VERSION 5.7 ;
BUSBITCHARS "[]" ;
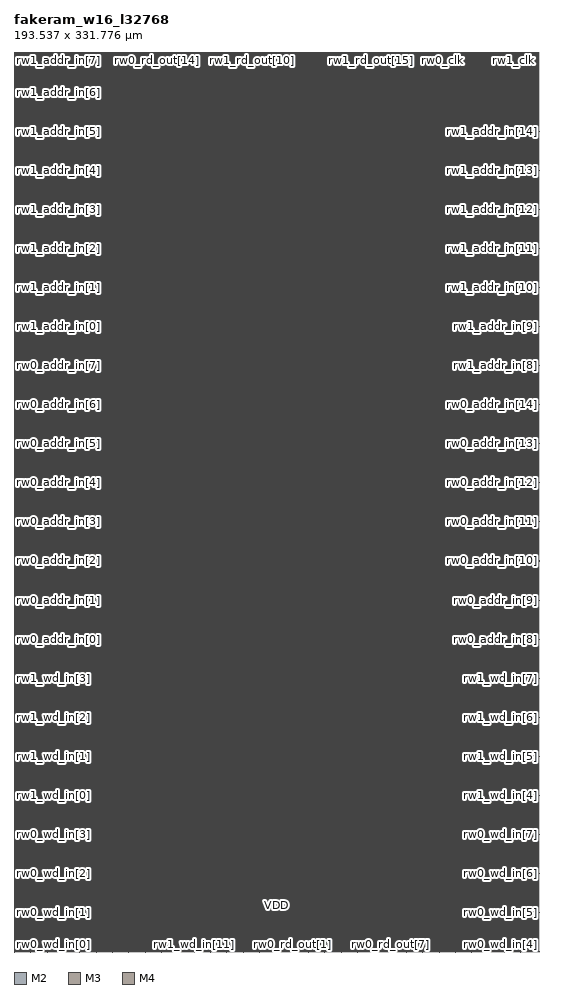
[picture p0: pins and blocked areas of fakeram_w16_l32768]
MACRO fakeram_w16_l32768
  FOREIGN fakeram_w16_l32768 0 0 ;
  SYMMETRY X Y R90 ;
  SIZE 193.537 BY 331.776 ;
  CLASS BLOCK ;
  PIN rw0_wd_in[0]
    DIRECTION INPUT ;
    USE SIGNAL ;
    SHAPE ABUTMENT ;
    PORT
      LAYER M2 ;
      RECT 0.000 0.138 0.036 0.150 ;
    END
  END rw0_wd_in[0]
  PIN rw0_wd_in[1]
    DIRECTION INPUT ;
    USE SIGNAL ;
    SHAPE ABUTMENT ;
    PORT
      LAYER M2 ;
      RECT 0.000 14.538 0.036 14.550 ;
    END
  END rw0_wd_in[1]
  PIN rw0_wd_in[2]
    DIRECTION INPUT ;
    USE SIGNAL ;
    SHAPE ABUTMENT ;
    PORT
      LAYER M2 ;
      RECT 0.000 28.938 0.036 28.950 ;
    END
  END rw0_wd_in[2]
  PIN rw0_wd_in[3]
    DIRECTION INPUT ;
    USE SIGNAL ;
    SHAPE ABUTMENT ;
    PORT
      LAYER M2 ;
      RECT 0.000 43.338 0.036 43.350 ;
    END
  END rw0_wd_in[3]
  PIN rw0_wd_in[4]
    DIRECTION INPUT ;
    USE SIGNAL ;
    SHAPE ABUTMENT ;
    PORT
      LAYER M2 ;
      RECT 193.501 0.138 193.537 0.150 ;
    END
  END rw0_wd_in[4]
  PIN rw0_wd_in[5]
    DIRECTION INPUT ;
    USE SIGNAL ;
    SHAPE ABUTMENT ;
    PORT
      LAYER M2 ;
      RECT 193.501 14.538 193.537 14.550 ;
    END
  END rw0_wd_in[5]
  PIN rw0_wd_in[6]
    DIRECTION INPUT ;
    USE SIGNAL ;
    SHAPE ABUTMENT ;
    PORT
      LAYER M2 ;
      RECT 193.501 28.938 193.537 28.950 ;
    END
  END rw0_wd_in[6]
  PIN rw0_wd_in[7]
    DIRECTION INPUT ;
    USE SIGNAL ;
    SHAPE ABUTMENT ;
    PORT
      LAYER M2 ;
      RECT 193.501 43.338 193.537 43.350 ;
    END
  END rw0_wd_in[7]
  PIN rw0_wd_in[8]
    DIRECTION INPUT ;
    USE SIGNAL ;
    SHAPE ABUTMENT ;
    PORT
      LAYER M3 ;
      RECT 0.161 0.000 0.175 0.042 ;
    END
  END rw0_wd_in[8]
  PIN rw0_wd_in[9]
    DIRECTION INPUT ;
    USE SIGNAL ;
    SHAPE ABUTMENT ;
    PORT
      LAYER M3 ;
      RECT 6.181 0.000 6.195 0.042 ;
    END
  END rw0_wd_in[9]
  PIN rw0_wd_in[10]
    DIRECTION INPUT ;
    USE SIGNAL ;
    SHAPE ABUTMENT ;
    PORT
      LAYER M3 ;
      RECT 12.201 0.000 12.215 0.042 ;
    END
  END rw0_wd_in[10]
  PIN rw0_wd_in[11]
    DIRECTION INPUT ;
    USE SIGNAL ;
    SHAPE ABUTMENT ;
    PORT
      LAYER M3 ;
      RECT 18.221 0.000 18.235 0.042 ;
    END
  END rw0_wd_in[11]
  PIN rw0_wd_in[12]
    DIRECTION INPUT ;
    USE SIGNAL ;
    SHAPE ABUTMENT ;
    PORT
      LAYER M3 ;
      RECT 24.241 0.000 24.255 0.042 ;
    END
  END rw0_wd_in[12]
  PIN rw0_wd_in[13]
    DIRECTION INPUT ;
    USE SIGNAL ;
    SHAPE ABUTMENT ;
    PORT
      LAYER M3 ;
      RECT 30.261 0.000 30.275 0.042 ;
    END
  END rw0_wd_in[13]
  PIN rw0_wd_in[14]
    DIRECTION INPUT ;
    USE SIGNAL ;
    SHAPE ABUTMENT ;
    PORT
      LAYER M3 ;
      RECT 36.281 0.000 36.295 0.042 ;
    END
  END rw0_wd_in[14]
  PIN rw0_wd_in[15]
    DIRECTION INPUT ;
    USE SIGNAL ;
    SHAPE ABUTMENT ;
    PORT
      LAYER M3 ;
      RECT 42.301 0.000 42.315 0.042 ;
    END
  END rw0_wd_in[15]
  PIN rw1_wd_in[0]
    DIRECTION INPUT ;
    USE SIGNAL ;
    SHAPE ABUTMENT ;
    PORT
      LAYER M2 ;
      RECT 0.000 57.738 0.036 57.750 ;
    END
  END rw1_wd_in[0]
  PIN rw1_wd_in[1]
    DIRECTION INPUT ;
    USE SIGNAL ;
    SHAPE ABUTMENT ;
    PORT
      LAYER M2 ;
      RECT 0.000 72.138 0.036 72.150 ;
    END
  END rw1_wd_in[1]
  PIN rw1_wd_in[2]
    DIRECTION INPUT ;
    USE SIGNAL ;
    SHAPE ABUTMENT ;
    PORT
      LAYER M2 ;
      RECT 0.000 86.538 0.036 86.550 ;
    END
  END rw1_wd_in[2]
  PIN rw1_wd_in[3]
    DIRECTION INPUT ;
    USE SIGNAL ;
    SHAPE ABUTMENT ;
    PORT
      LAYER M2 ;
      RECT 0.000 100.938 0.036 100.950 ;
    END
  END rw1_wd_in[3]
  PIN rw1_wd_in[4]
    DIRECTION INPUT ;
    USE SIGNAL ;
    SHAPE ABUTMENT ;
    PORT
      LAYER M2 ;
      RECT 193.501 57.738 193.537 57.750 ;
    END
  END rw1_wd_in[4]
  PIN rw1_wd_in[5]
    DIRECTION INPUT ;
    USE SIGNAL ;
    SHAPE ABUTMENT ;
    PORT
      LAYER M2 ;
      RECT 193.501 72.138 193.537 72.150 ;
    END
  END rw1_wd_in[5]
  PIN rw1_wd_in[6]
    DIRECTION INPUT ;
    USE SIGNAL ;
    SHAPE ABUTMENT ;
    PORT
      LAYER M2 ;
      RECT 193.501 86.538 193.537 86.550 ;
    END
  END rw1_wd_in[6]
  PIN rw1_wd_in[7]
    DIRECTION INPUT ;
    USE SIGNAL ;
    SHAPE ABUTMENT ;
    PORT
      LAYER M2 ;
      RECT 193.501 100.938 193.537 100.950 ;
    END
  END rw1_wd_in[7]
  PIN rw1_wd_in[8]
    DIRECTION INPUT ;
    USE SIGNAL ;
    SHAPE ABUTMENT ;
    PORT
      LAYER M3 ;
      RECT 48.321 0.000 48.335 0.042 ;
    END
  END rw1_wd_in[8]
  PIN rw1_wd_in[9]
    DIRECTION INPUT ;
    USE SIGNAL ;
    SHAPE ABUTMENT ;
    PORT
      LAYER M3 ;
      RECT 54.341 0.000 54.355 0.042 ;
    END
  END rw1_wd_in[9]
  PIN rw1_wd_in[10]
    DIRECTION INPUT ;
    USE SIGNAL ;
    SHAPE ABUTMENT ;
    PORT
      LAYER M3 ;
      RECT 60.361 0.000 60.375 0.042 ;
    END
  END rw1_wd_in[10]
  PIN rw1_wd_in[11]
    DIRECTION INPUT ;
    USE SIGNAL ;
    SHAPE ABUTMENT ;
    PORT
      LAYER M3 ;
      RECT 66.381 0.000 66.395 0.042 ;
    END
  END rw1_wd_in[11]
  PIN rw1_wd_in[12]
    DIRECTION INPUT ;
    USE SIGNAL ;
    SHAPE ABUTMENT ;
    PORT
      LAYER M3 ;
      RECT 72.401 0.000 72.415 0.042 ;
    END
  END rw1_wd_in[12]
  PIN rw1_wd_in[13]
    DIRECTION INPUT ;
    USE SIGNAL ;
    SHAPE ABUTMENT ;
    PORT
      LAYER M3 ;
      RECT 78.421 0.000 78.435 0.042 ;
    END
  END rw1_wd_in[13]
  PIN rw1_wd_in[14]
    DIRECTION INPUT ;
    USE SIGNAL ;
    SHAPE ABUTMENT ;
    PORT
      LAYER M3 ;
      RECT 84.441 0.000 84.455 0.042 ;
    END
  END rw1_wd_in[14]
  PIN rw1_wd_in[15]
    DIRECTION INPUT ;
    USE SIGNAL ;
    SHAPE ABUTMENT ;
    PORT
      LAYER M3 ;
      RECT 90.461 0.000 90.475 0.042 ;
    END
  END rw1_wd_in[15]
  PIN rw0_rd_out[0]
    DIRECTION OUTPUT ;
    USE SIGNAL ;
    SHAPE ABUTMENT ;
    PORT
      LAYER M3 ;
      RECT 96.481 0.000 96.495 0.042 ;
    END
  END rw0_rd_out[0]
  PIN rw0_rd_out[1]
    DIRECTION OUTPUT ;
    USE SIGNAL ;
    SHAPE ABUTMENT ;
    PORT
      LAYER M3 ;
      RECT 102.501 0.000 102.515 0.042 ;
    END
  END rw0_rd_out[1]
  PIN rw0_rd_out[2]
    DIRECTION OUTPUT ;
    USE SIGNAL ;
    SHAPE ABUTMENT ;
    PORT
      LAYER M3 ;
      RECT 108.521 0.000 108.535 0.042 ;
    END
  END rw0_rd_out[2]
  PIN rw0_rd_out[3]
    DIRECTION OUTPUT ;
    USE SIGNAL ;
    SHAPE ABUTMENT ;
    PORT
      LAYER M3 ;
      RECT 114.541 0.000 114.555 0.042 ;
    END
  END rw0_rd_out[3]
  PIN rw0_rd_out[4]
    DIRECTION OUTPUT ;
    USE SIGNAL ;
    SHAPE ABUTMENT ;
    PORT
      LAYER M3 ;
      RECT 120.561 0.000 120.575 0.042 ;
    END
  END rw0_rd_out[4]
  PIN rw0_rd_out[5]
    DIRECTION OUTPUT ;
    USE SIGNAL ;
    SHAPE ABUTMENT ;
    PORT
      LAYER M3 ;
      RECT 126.581 0.000 126.595 0.042 ;
    END
  END rw0_rd_out[5]
  PIN rw0_rd_out[6]
    DIRECTION OUTPUT ;
    USE SIGNAL ;
    SHAPE ABUTMENT ;
    PORT
      LAYER M3 ;
      RECT 132.601 0.000 132.615 0.042 ;
    END
  END rw0_rd_out[6]
  PIN rw0_rd_out[7]
    DIRECTION OUTPUT ;
    USE SIGNAL ;
    SHAPE ABUTMENT ;
    PORT
      LAYER M3 ;
      RECT 138.621 0.000 138.635 0.042 ;
    END
  END rw0_rd_out[7]
  PIN rw0_rd_out[8]
    DIRECTION OUTPUT ;
    USE SIGNAL ;
    SHAPE ABUTMENT ;
    PORT
      LAYER M3 ;
      RECT 0.161 331.734 0.175 331.776 ;
    END
  END rw0_rd_out[8]
  PIN rw0_rd_out[9]
    DIRECTION OUTPUT ;
    USE SIGNAL ;
    SHAPE ABUTMENT ;
    PORT
      LAYER M3 ;
      RECT 8.925 331.734 8.939 331.776 ;
    END
  END rw0_rd_out[9]
  PIN rw0_rd_out[10]
    DIRECTION OUTPUT ;
    USE SIGNAL ;
    SHAPE ABUTMENT ;
    PORT
      LAYER M3 ;
      RECT 17.689 331.734 17.703 331.776 ;
    END
  END rw0_rd_out[10]
  PIN rw0_rd_out[11]
    DIRECTION OUTPUT ;
    USE SIGNAL ;
    SHAPE ABUTMENT ;
    PORT
      LAYER M3 ;
      RECT 26.453 331.734 26.467 331.776 ;
    END
  END rw0_rd_out[11]
  PIN rw0_rd_out[12]
    DIRECTION OUTPUT ;
    USE SIGNAL ;
    SHAPE ABUTMENT ;
    PORT
      LAYER M3 ;
      RECT 35.217 331.734 35.231 331.776 ;
    END
  END rw0_rd_out[12]
  PIN rw0_rd_out[13]
    DIRECTION OUTPUT ;
    USE SIGNAL ;
    SHAPE ABUTMENT ;
    PORT
      LAYER M3 ;
      RECT 43.981 331.734 43.995 331.776 ;
    END
  END rw0_rd_out[13]
  PIN rw0_rd_out[14]
    DIRECTION OUTPUT ;
    USE SIGNAL ;
    SHAPE ABUTMENT ;
    PORT
      LAYER M3 ;
      RECT 52.745 331.734 52.759 331.776 ;
    END
  END rw0_rd_out[14]
  PIN rw0_rd_out[15]
    DIRECTION OUTPUT ;
    USE SIGNAL ;
    SHAPE ABUTMENT ;
    PORT
      LAYER M3 ;
      RECT 61.509 331.734 61.523 331.776 ;
    END
  END rw0_rd_out[15]
  PIN rw1_rd_out[0]
    DIRECTION OUTPUT ;
    USE SIGNAL ;
    SHAPE ABUTMENT ;
    PORT
      LAYER M3 ;
      RECT 144.641 0.000 144.655 0.042 ;
    END
  END rw1_rd_out[0]
  PIN rw1_rd_out[1]
    DIRECTION OUTPUT ;
    USE SIGNAL ;
    SHAPE ABUTMENT ;
    PORT
      LAYER M3 ;
      RECT 150.661 0.000 150.675 0.042 ;
    END
  END rw1_rd_out[1]
  PIN rw1_rd_out[2]
    DIRECTION OUTPUT ;
    USE SIGNAL ;
    SHAPE ABUTMENT ;
    PORT
      LAYER M3 ;
      RECT 156.681 0.000 156.695 0.042 ;
    END
  END rw1_rd_out[2]
  PIN rw1_rd_out[3]
    DIRECTION OUTPUT ;
    USE SIGNAL ;
    SHAPE ABUTMENT ;
    PORT
      LAYER M3 ;
      RECT 162.701 0.000 162.715 0.042 ;
    END
  END rw1_rd_out[3]
  PIN rw1_rd_out[4]
    DIRECTION OUTPUT ;
    USE SIGNAL ;
    SHAPE ABUTMENT ;
    PORT
      LAYER M3 ;
      RECT 168.721 0.000 168.735 0.042 ;
    END
  END rw1_rd_out[4]
  PIN rw1_rd_out[5]
    DIRECTION OUTPUT ;
    USE SIGNAL ;
    SHAPE ABUTMENT ;
    PORT
      LAYER M3 ;
      RECT 174.741 0.000 174.755 0.042 ;
    END
  END rw1_rd_out[5]
  PIN rw1_rd_out[6]
    DIRECTION OUTPUT ;
    USE SIGNAL ;
    SHAPE ABUTMENT ;
    PORT
      LAYER M3 ;
      RECT 180.761 0.000 180.775 0.042 ;
    END
  END rw1_rd_out[6]
  PIN rw1_rd_out[7]
    DIRECTION OUTPUT ;
    USE SIGNAL ;
    SHAPE ABUTMENT ;
    PORT
      LAYER M3 ;
      RECT 186.781 0.000 186.795 0.042 ;
    END
  END rw1_rd_out[7]
  PIN rw1_rd_out[8]
    DIRECTION OUTPUT ;
    USE SIGNAL ;
    SHAPE ABUTMENT ;
    PORT
      LAYER M3 ;
      RECT 70.273 331.734 70.287 331.776 ;
    END
  END rw1_rd_out[8]
  PIN rw1_rd_out[9]
    DIRECTION OUTPUT ;
    USE SIGNAL ;
    SHAPE ABUTMENT ;
    PORT
      LAYER M3 ;
      RECT 79.037 331.734 79.051 331.776 ;
    END
  END rw1_rd_out[9]
  PIN rw1_rd_out[10]
    DIRECTION OUTPUT ;
    USE SIGNAL ;
    SHAPE ABUTMENT ;
    PORT
      LAYER M3 ;
      RECT 87.801 331.734 87.815 331.776 ;
    END
  END rw1_rd_out[10]
  PIN rw1_rd_out[11]
    DIRECTION OUTPUT ;
    USE SIGNAL ;
    SHAPE ABUTMENT ;
    PORT
      LAYER M3 ;
      RECT 96.565 331.734 96.579 331.776 ;
    END
  END rw1_rd_out[11]
  PIN rw1_rd_out[12]
    DIRECTION OUTPUT ;
    USE SIGNAL ;
    SHAPE ABUTMENT ;
    PORT
      LAYER M3 ;
      RECT 105.329 331.734 105.343 331.776 ;
    END
  END rw1_rd_out[12]
  PIN rw1_rd_out[13]
    DIRECTION OUTPUT ;
    USE SIGNAL ;
    SHAPE ABUTMENT ;
    PORT
      LAYER M3 ;
      RECT 114.093 331.734 114.107 331.776 ;
    END
  END rw1_rd_out[13]
  PIN rw1_rd_out[14]
    DIRECTION OUTPUT ;
    USE SIGNAL ;
    SHAPE ABUTMENT ;
    PORT
      LAYER M3 ;
      RECT 122.857 331.734 122.871 331.776 ;
    END
  END rw1_rd_out[14]
  PIN rw1_rd_out[15]
    DIRECTION OUTPUT ;
    USE SIGNAL ;
    SHAPE ABUTMENT ;
    PORT
      LAYER M3 ;
      RECT 131.621 331.734 131.635 331.776 ;
    END
  END rw1_rd_out[15]
  PIN rw0_addr_in[0]
    DIRECTION INPUT ;
    USE SIGNAL ;
    SHAPE ABUTMENT ;
    PORT
      LAYER M2 ;
      RECT 0.000 115.338 0.036 115.350 ;
    END
  END rw0_addr_in[0]
  PIN rw0_addr_in[1]
    DIRECTION INPUT ;
    USE SIGNAL ;
    SHAPE ABUTMENT ;
    PORT
      LAYER M2 ;
      RECT 0.000 129.738 0.036 129.750 ;
    END
  END rw0_addr_in[1]
  PIN rw0_addr_in[2]
    DIRECTION INPUT ;
    USE SIGNAL ;
    SHAPE ABUTMENT ;
    PORT
      LAYER M2 ;
      RECT 0.000 144.138 0.036 144.150 ;
    END
  END rw0_addr_in[2]
  PIN rw0_addr_in[3]
    DIRECTION INPUT ;
    USE SIGNAL ;
    SHAPE ABUTMENT ;
    PORT
      LAYER M2 ;
      RECT 0.000 158.538 0.036 158.550 ;
    END
  END rw0_addr_in[3]
  PIN rw0_addr_in[4]
    DIRECTION INPUT ;
    USE SIGNAL ;
    SHAPE ABUTMENT ;
    PORT
      LAYER M2 ;
      RECT 0.000 172.938 0.036 172.950 ;
    END
  END rw0_addr_in[4]
  PIN rw0_addr_in[5]
    DIRECTION INPUT ;
    USE SIGNAL ;
    SHAPE ABUTMENT ;
    PORT
      LAYER M2 ;
      RECT 0.000 187.338 0.036 187.350 ;
    END
  END rw0_addr_in[5]
  PIN rw0_addr_in[6]
    DIRECTION INPUT ;
    USE SIGNAL ;
    SHAPE ABUTMENT ;
    PORT
      LAYER M2 ;
      RECT 0.000 201.738 0.036 201.750 ;
    END
  END rw0_addr_in[6]
  PIN rw0_addr_in[7]
    DIRECTION INPUT ;
    USE SIGNAL ;
    SHAPE ABUTMENT ;
    PORT
      LAYER M2 ;
      RECT 0.000 216.138 0.036 216.150 ;
    END
  END rw0_addr_in[7]
  PIN rw0_addr_in[8]
    DIRECTION INPUT ;
    USE SIGNAL ;
    SHAPE ABUTMENT ;
    PORT
      LAYER M2 ;
      RECT 193.501 115.338 193.537 115.350 ;
    END
  END rw0_addr_in[8]
  PIN rw0_addr_in[9]
    DIRECTION INPUT ;
    USE SIGNAL ;
    SHAPE ABUTMENT ;
    PORT
      LAYER M2 ;
      RECT 193.501 129.738 193.537 129.750 ;
    END
  END rw0_addr_in[9]
  PIN rw0_addr_in[10]
    DIRECTION INPUT ;
    USE SIGNAL ;
    SHAPE ABUTMENT ;
    PORT
      LAYER M2 ;
      RECT 193.501 144.138 193.537 144.150 ;
    END
  END rw0_addr_in[10]
  PIN rw0_addr_in[11]
    DIRECTION INPUT ;
    USE SIGNAL ;
    SHAPE ABUTMENT ;
    PORT
      LAYER M2 ;
      RECT 193.501 158.538 193.537 158.550 ;
    END
  END rw0_addr_in[11]
  PIN rw0_addr_in[12]
    DIRECTION INPUT ;
    USE SIGNAL ;
    SHAPE ABUTMENT ;
    PORT
      LAYER M2 ;
      RECT 193.501 172.938 193.537 172.950 ;
    END
  END rw0_addr_in[12]
  PIN rw0_addr_in[13]
    DIRECTION INPUT ;
    USE SIGNAL ;
    SHAPE ABUTMENT ;
    PORT
      LAYER M2 ;
      RECT 193.501 187.338 193.537 187.350 ;
    END
  END rw0_addr_in[13]
  PIN rw0_addr_in[14]
    DIRECTION INPUT ;
    USE SIGNAL ;
    SHAPE ABUTMENT ;
    PORT
      LAYER M2 ;
      RECT 193.501 201.738 193.537 201.750 ;
    END
  END rw0_addr_in[14]
  PIN rw1_addr_in[0]
    DIRECTION INPUT ;
    USE SIGNAL ;
    SHAPE ABUTMENT ;
    PORT
      LAYER M2 ;
      RECT 0.000 230.538 0.036 230.550 ;
    END
  END rw1_addr_in[0]
  PIN rw1_addr_in[1]
    DIRECTION INPUT ;
    USE SIGNAL ;
    SHAPE ABUTMENT ;
    PORT
      LAYER M2 ;
      RECT 0.000 244.938 0.036 244.950 ;
    END
  END rw1_addr_in[1]
  PIN rw1_addr_in[2]
    DIRECTION INPUT ;
    USE SIGNAL ;
    SHAPE ABUTMENT ;
    PORT
      LAYER M2 ;
      RECT 0.000 259.338 0.036 259.350 ;
    END
  END rw1_addr_in[2]
  PIN rw1_addr_in[3]
    DIRECTION INPUT ;
    USE SIGNAL ;
    SHAPE ABUTMENT ;
    PORT
      LAYER M2 ;
      RECT 0.000 273.738 0.036 273.750 ;
    END
  END rw1_addr_in[3]
  PIN rw1_addr_in[4]
    DIRECTION INPUT ;
    USE SIGNAL ;
    SHAPE ABUTMENT ;
    PORT
      LAYER M2 ;
      RECT 0.000 288.138 0.036 288.150 ;
    END
  END rw1_addr_in[4]
  PIN rw1_addr_in[5]
    DIRECTION INPUT ;
    USE SIGNAL ;
    SHAPE ABUTMENT ;
    PORT
      LAYER M2 ;
      RECT 0.000 302.538 0.036 302.550 ;
    END
  END rw1_addr_in[5]
  PIN rw1_addr_in[6]
    DIRECTION INPUT ;
    USE SIGNAL ;
    SHAPE ABUTMENT ;
    PORT
      LAYER M2 ;
      RECT 0.000 316.938 0.036 316.950 ;
    END
  END rw1_addr_in[6]
  PIN rw1_addr_in[7]
    DIRECTION INPUT ;
    USE SIGNAL ;
    SHAPE ABUTMENT ;
    PORT
      LAYER M2 ;
      RECT 0.000 331.338 0.036 331.350 ;
    END
  END rw1_addr_in[7]
  PIN rw1_addr_in[8]
    DIRECTION INPUT ;
    USE SIGNAL ;
    SHAPE ABUTMENT ;
    PORT
      LAYER M2 ;
      RECT 193.501 216.138 193.537 216.150 ;
    END
  END rw1_addr_in[8]
  PIN rw1_addr_in[9]
    DIRECTION INPUT ;
    USE SIGNAL ;
    SHAPE ABUTMENT ;
    PORT
      LAYER M2 ;
      RECT 193.501 230.538 193.537 230.550 ;
    END
  END rw1_addr_in[9]
  PIN rw1_addr_in[10]
    DIRECTION INPUT ;
    USE SIGNAL ;
    SHAPE ABUTMENT ;
    PORT
      LAYER M2 ;
      RECT 193.501 244.938 193.537 244.950 ;
    END
  END rw1_addr_in[10]
  PIN rw1_addr_in[11]
    DIRECTION INPUT ;
    USE SIGNAL ;
    SHAPE ABUTMENT ;
    PORT
      LAYER M2 ;
      RECT 193.501 259.338 193.537 259.350 ;
    END
  END rw1_addr_in[11]
  PIN rw1_addr_in[12]
    DIRECTION INPUT ;
    USE SIGNAL ;
    SHAPE ABUTMENT ;
    PORT
      LAYER M2 ;
      RECT 193.501 273.738 193.537 273.750 ;
    END
  END rw1_addr_in[12]
  PIN rw1_addr_in[13]
    DIRECTION INPUT ;
    USE SIGNAL ;
    SHAPE ABUTMENT ;
    PORT
      LAYER M2 ;
      RECT 193.501 288.138 193.537 288.150 ;
    END
  END rw1_addr_in[13]
  PIN rw1_addr_in[14]
    DIRECTION INPUT ;
    USE SIGNAL ;
    SHAPE ABUTMENT ;
    PORT
      LAYER M2 ;
      RECT 193.501 302.538 193.537 302.550 ;
    END
  END rw1_addr_in[14]
  PIN rw0_we_in
    DIRECTION INPUT ;
    USE SIGNAL ;
    SHAPE ABUTMENT ;
    PORT
      LAYER M3 ;
      RECT 140.385 331.734 140.399 331.776 ;
    END
  END rw0_we_in
  PIN rw0_ce_in
    DIRECTION INPUT ;
    USE SIGNAL ;
    SHAPE ABUTMENT ;
    PORT
      LAYER M3 ;
      RECT 149.149 331.734 149.163 331.776 ;
    END
  END rw0_ce_in
  PIN rw0_clk
    DIRECTION INPUT ;
    USE SIGNAL ;
    SHAPE ABUTMENT ;
    PORT
      LAYER M3 ;
      RECT 157.913 331.734 157.927 331.776 ;
    END
  END rw0_clk
  PIN rw1_we_in
    DIRECTION INPUT ;
    USE SIGNAL ;
    SHAPE ABUTMENT ;
    PORT
      LAYER M3 ;
      RECT 166.677 331.734 166.691 331.776 ;
    END
  END rw1_we_in
  PIN rw1_ce_in
    DIRECTION INPUT ;
    USE SIGNAL ;
    SHAPE ABUTMENT ;
    PORT
      LAYER M3 ;
      RECT 175.441 331.734 175.455 331.776 ;
    END
  END rw1_ce_in
  PIN rw1_clk
    DIRECTION INPUT ;
    USE SIGNAL ;
    SHAPE ABUTMENT ;
    PORT
      LAYER M3 ;
      RECT 184.205 331.734 184.219 331.776 ;
    END
  END rw1_clk
  PIN VSS
    DIRECTION INOUT ;
    USE GROUND ;
    PORT
      LAYER M4 ;
      RECT 0.168 0.120 193.369 0.168 ;
      RECT 0.168 0.504 193.369 0.552 ;
      RECT 0.168 0.888 193.369 0.936 ;
      RECT 0.168 1.272 193.369 1.320 ;
      RECT 0.168 1.656 193.369 1.704 ;
      RECT 0.168 2.040 193.369 2.088 ;
      RECT 0.168 2.424 193.369 2.472 ;
      RECT 0.168 2.808 193.369 2.856 ;
      RECT 0.168 3.192 193.369 3.240 ;
      RECT 0.168 3.576 193.369 3.624 ;
      RECT 0.168 3.960 193.369 4.008 ;
      RECT 0.168 4.344 193.369 4.392 ;
      RECT 0.168 4.728 193.369 4.776 ;
      RECT 0.168 5.112 193.369 5.160 ;
      RECT 0.168 5.496 193.369 5.544 ;
      RECT 0.168 5.880 193.369 5.928 ;
      RECT 0.168 6.264 193.369 6.312 ;
      RECT 0.168 6.648 193.369 6.696 ;
      RECT 0.168 7.032 193.369 7.080 ;
      RECT 0.168 7.416 193.369 7.464 ;
      RECT 0.168 7.800 193.369 7.848 ;
      RECT 0.168 8.184 193.369 8.232 ;
      RECT 0.168 8.568 193.369 8.616 ;
      RECT 0.168 8.952 193.369 9.000 ;
      RECT 0.168 9.336 193.369 9.384 ;
      RECT 0.168 9.720 193.369 9.768 ;
      RECT 0.168 10.104 193.369 10.152 ;
      RECT 0.168 10.488 193.369 10.536 ;
      RECT 0.168 10.872 193.369 10.920 ;
      RECT 0.168 11.256 193.369 11.304 ;
      RECT 0.168 11.640 193.369 11.688 ;
      RECT 0.168 12.024 193.369 12.072 ;
      RECT 0.168 12.408 193.369 12.456 ;
      RECT 0.168 12.792 193.369 12.840 ;
      RECT 0.168 13.176 193.369 13.224 ;
      RECT 0.168 13.560 193.369 13.608 ;
      RECT 0.168 13.944 193.369 13.992 ;
      RECT 0.168 14.328 193.369 14.376 ;
      RECT 0.168 14.712 193.369 14.760 ;
      RECT 0.168 15.096 193.369 15.144 ;
      RECT 0.168 15.480 193.369 15.528 ;
      RECT 0.168 15.864 193.369 15.912 ;
      RECT 0.168 16.248 193.369 16.296 ;
      RECT 0.168 16.632 193.369 16.680 ;
      RECT 0.168 17.016 193.369 17.064 ;
      RECT 0.168 17.400 193.369 17.448 ;
      RECT 0.168 17.784 193.369 17.832 ;
      RECT 0.168 18.168 193.369 18.216 ;
      RECT 0.168 18.552 193.369 18.600 ;
      RECT 0.168 18.936 193.369 18.984 ;
      RECT 0.168 19.320 193.369 19.368 ;
      RECT 0.168 19.704 193.369 19.752 ;
      RECT 0.168 20.088 193.369 20.136 ;
      RECT 0.168 20.472 193.369 20.520 ;
      RECT 0.168 20.856 193.369 20.904 ;
      RECT 0.168 21.240 193.369 21.288 ;
      RECT 0.168 21.624 193.369 21.672 ;
      RECT 0.168 22.008 193.369 22.056 ;
      RECT 0.168 22.392 193.369 22.440 ;
      RECT 0.168 22.776 193.369 22.824 ;
      RECT 0.168 23.160 193.369 23.208 ;
      RECT 0.168 23.544 193.369 23.592 ;
      RECT 0.168 23.928 193.369 23.976 ;
      RECT 0.168 24.312 193.369 24.360 ;
      RECT 0.168 24.696 193.369 24.744 ;
      RECT 0.168 25.080 193.369 25.128 ;
      RECT 0.168 25.464 193.369 25.512 ;
      RECT 0.168 25.848 193.369 25.896 ;
      RECT 0.168 26.232 193.369 26.280 ;
      RECT 0.168 26.616 193.369 26.664 ;
      RECT 0.168 27.000 193.369 27.048 ;
      RECT 0.168 27.384 193.369 27.432 ;
      RECT 0.168 27.768 193.369 27.816 ;
      RECT 0.168 28.152 193.369 28.200 ;
      RECT 0.168 28.536 193.369 28.584 ;
      RECT 0.168 28.920 193.369 28.968 ;
      RECT 0.168 29.304 193.369 29.352 ;
      RECT 0.168 29.688 193.369 29.736 ;
      RECT 0.168 30.072 193.369 30.120 ;
      RECT 0.168 30.456 193.369 30.504 ;
      RECT 0.168 30.840 193.369 30.888 ;
      RECT 0.168 31.224 193.369 31.272 ;
      RECT 0.168 31.608 193.369 31.656 ;
      RECT 0.168 31.992 193.369 32.040 ;
      RECT 0.168 32.376 193.369 32.424 ;
      RECT 0.168 32.760 193.369 32.808 ;
      RECT 0.168 33.144 193.369 33.192 ;
      RECT 0.168 33.528 193.369 33.576 ;
      RECT 0.168 33.912 193.369 33.960 ;
      RECT 0.168 34.296 193.369 34.344 ;
      RECT 0.168 34.680 193.369 34.728 ;
      RECT 0.168 35.064 193.369 35.112 ;
      RECT 0.168 35.448 193.369 35.496 ;
      RECT 0.168 35.832 193.369 35.880 ;
      RECT 0.168 36.216 193.369 36.264 ;
      RECT 0.168 36.600 193.369 36.648 ;
      RECT 0.168 36.984 193.369 37.032 ;
      RECT 0.168 37.368 193.369 37.416 ;
      RECT 0.168 37.752 193.369 37.800 ;
      RECT 0.168 38.136 193.369 38.184 ;
      RECT 0.168 38.520 193.369 38.568 ;
      RECT 0.168 38.904 193.369 38.952 ;
      RECT 0.168 39.288 193.369 39.336 ;
      RECT 0.168 39.672 193.369 39.720 ;
      RECT 0.168 40.056 193.369 40.104 ;
      RECT 0.168 40.440 193.369 40.488 ;
      RECT 0.168 40.824 193.369 40.872 ;
      RECT 0.168 41.208 193.369 41.256 ;
      RECT 0.168 41.592 193.369 41.640 ;
      RECT 0.168 41.976 193.369 42.024 ;
      RECT 0.168 42.360 193.369 42.408 ;
      RECT 0.168 42.744 193.369 42.792 ;
      RECT 0.168 43.128 193.369 43.176 ;
      RECT 0.168 43.512 193.369 43.560 ;
      RECT 0.168 43.896 193.369 43.944 ;
      RECT 0.168 44.280 193.369 44.328 ;
      RECT 0.168 44.664 193.369 44.712 ;
      RECT 0.168 45.048 193.369 45.096 ;
      RECT 0.168 45.432 193.369 45.480 ;
      RECT 0.168 45.816 193.369 45.864 ;
      RECT 0.168 46.200 193.369 46.248 ;
      RECT 0.168 46.584 193.369 46.632 ;
      RECT 0.168 46.968 193.369 47.016 ;
      RECT 0.168 47.352 193.369 47.400 ;
      RECT 0.168 47.736 193.369 47.784 ;
      RECT 0.168 48.120 193.369 48.168 ;
      RECT 0.168 48.504 193.369 48.552 ;
      RECT 0.168 48.888 193.369 48.936 ;
      RECT 0.168 49.272 193.369 49.320 ;
      RECT 0.168 49.656 193.369 49.704 ;
      RECT 0.168 50.040 193.369 50.088 ;
      RECT 0.168 50.424 193.369 50.472 ;
      RECT 0.168 50.808 193.369 50.856 ;
      RECT 0.168 51.192 193.369 51.240 ;
      RECT 0.168 51.576 193.369 51.624 ;
      RECT 0.168 51.960 193.369 52.008 ;
      RECT 0.168 52.344 193.369 52.392 ;
      RECT 0.168 52.728 193.369 52.776 ;
      RECT 0.168 53.112 193.369 53.160 ;
      RECT 0.168 53.496 193.369 53.544 ;
      RECT 0.168 53.880 193.369 53.928 ;
      RECT 0.168 54.264 193.369 54.312 ;
      RECT 0.168 54.648 193.369 54.696 ;
      RECT 0.168 55.032 193.369 55.080 ;
      RECT 0.168 55.416 193.369 55.464 ;
      RECT 0.168 55.800 193.369 55.848 ;
      RECT 0.168 56.184 193.369 56.232 ;
      RECT 0.168 56.568 193.369 56.616 ;
      RECT 0.168 56.952 193.369 57.000 ;
      RECT 0.168 57.336 193.369 57.384 ;
      RECT 0.168 57.720 193.369 57.768 ;
      RECT 0.168 58.104 193.369 58.152 ;
      RECT 0.168 58.488 193.369 58.536 ;
      RECT 0.168 58.872 193.369 58.920 ;
      RECT 0.168 59.256 193.369 59.304 ;
      RECT 0.168 59.640 193.369 59.688 ;
      RECT 0.168 60.024 193.369 60.072 ;
      RECT 0.168 60.408 193.369 60.456 ;
      RECT 0.168 60.792 193.369 60.840 ;
      RECT 0.168 61.176 193.369 61.224 ;
      RECT 0.168 61.560 193.369 61.608 ;
      RECT 0.168 61.944 193.369 61.992 ;
      RECT 0.168 62.328 193.369 62.376 ;
      RECT 0.168 62.712 193.369 62.760 ;
      RECT 0.168 63.096 193.369 63.144 ;
      RECT 0.168 63.480 193.369 63.528 ;
      RECT 0.168 63.864 193.369 63.912 ;
      RECT 0.168 64.248 193.369 64.296 ;
      RECT 0.168 64.632 193.369 64.680 ;
      RECT 0.168 65.016 193.369 65.064 ;
      RECT 0.168 65.400 193.369 65.448 ;
      RECT 0.168 65.784 193.369 65.832 ;
      RECT 0.168 66.168 193.369 66.216 ;
      RECT 0.168 66.552 193.369 66.600 ;
      RECT 0.168 66.936 193.369 66.984 ;
      RECT 0.168 67.320 193.369 67.368 ;
      RECT 0.168 67.704 193.369 67.752 ;
      RECT 0.168 68.088 193.369 68.136 ;
      RECT 0.168 68.472 193.369 68.520 ;
      RECT 0.168 68.856 193.369 68.904 ;
      RECT 0.168 69.240 193.369 69.288 ;
      RECT 0.168 69.624 193.369 69.672 ;
      RECT 0.168 70.008 193.369 70.056 ;
      RECT 0.168 70.392 193.369 70.440 ;
      RECT 0.168 70.776 193.369 70.824 ;
      RECT 0.168 71.160 193.369 71.208 ;
      RECT 0.168 71.544 193.369 71.592 ;
      RECT 0.168 71.928 193.369 71.976 ;
      RECT 0.168 72.312 193.369 72.360 ;
      RECT 0.168 72.696 193.369 72.744 ;
      RECT 0.168 73.080 193.369 73.128 ;
      RECT 0.168 73.464 193.369 73.512 ;
      RECT 0.168 73.848 193.369 73.896 ;
      RECT 0.168 74.232 193.369 74.280 ;
      RECT 0.168 74.616 193.369 74.664 ;
      RECT 0.168 75.000 193.369 75.048 ;
      RECT 0.168 75.384 193.369 75.432 ;
      RECT 0.168 75.768 193.369 75.816 ;
      RECT 0.168 76.152 193.369 76.200 ;
      RECT 0.168 76.536 193.369 76.584 ;
      RECT 0.168 76.920 193.369 76.968 ;
      RECT 0.168 77.304 193.369 77.352 ;
      RECT 0.168 77.688 193.369 77.736 ;
      RECT 0.168 78.072 193.369 78.120 ;
      RECT 0.168 78.456 193.369 78.504 ;
      RECT 0.168 78.840 193.369 78.888 ;
      RECT 0.168 79.224 193.369 79.272 ;
      RECT 0.168 79.608 193.369 79.656 ;
      RECT 0.168 79.992 193.369 80.040 ;
      RECT 0.168 80.376 193.369 80.424 ;
      RECT 0.168 80.760 193.369 80.808 ;
      RECT 0.168 81.144 193.369 81.192 ;
      RECT 0.168 81.528 193.369 81.576 ;
      RECT 0.168 81.912 193.369 81.960 ;
      RECT 0.168 82.296 193.369 82.344 ;
      RECT 0.168 82.680 193.369 82.728 ;
      RECT 0.168 83.064 193.369 83.112 ;
      RECT 0.168 83.448 193.369 83.496 ;
      RECT 0.168 83.832 193.369 83.880 ;
      RECT 0.168 84.216 193.369 84.264 ;
      RECT 0.168 84.600 193.369 84.648 ;
      RECT 0.168 84.984 193.369 85.032 ;
      RECT 0.168 85.368 193.369 85.416 ;
      RECT 0.168 85.752 193.369 85.800 ;
      RECT 0.168 86.136 193.369 86.184 ;
      RECT 0.168 86.520 193.369 86.568 ;
      RECT 0.168 86.904 193.369 86.952 ;
      RECT 0.168 87.288 193.369 87.336 ;
      RECT 0.168 87.672 193.369 87.720 ;
      RECT 0.168 88.056 193.369 88.104 ;
      RECT 0.168 88.440 193.369 88.488 ;
      RECT 0.168 88.824 193.369 88.872 ;
      RECT 0.168 89.208 193.369 89.256 ;
      RECT 0.168 89.592 193.369 89.640 ;
      RECT 0.168 89.976 193.369 90.024 ;
      RECT 0.168 90.360 193.369 90.408 ;
      RECT 0.168 90.744 193.369 90.792 ;
      RECT 0.168 91.128 193.369 91.176 ;
      RECT 0.168 91.512 193.369 91.560 ;
      RECT 0.168 91.896 193.369 91.944 ;
      RECT 0.168 92.280 193.369 92.328 ;
      RECT 0.168 92.664 193.369 92.712 ;
      RECT 0.168 93.048 193.369 93.096 ;
      RECT 0.168 93.432 193.369 93.480 ;
      RECT 0.168 93.816 193.369 93.864 ;
      RECT 0.168 94.200 193.369 94.248 ;
      RECT 0.168 94.584 193.369 94.632 ;
      RECT 0.168 94.968 193.369 95.016 ;
      RECT 0.168 95.352 193.369 95.400 ;
      RECT 0.168 95.736 193.369 95.784 ;
      RECT 0.168 96.120 193.369 96.168 ;
      RECT 0.168 96.504 193.369 96.552 ;
      RECT 0.168 96.888 193.369 96.936 ;
      RECT 0.168 97.272 193.369 97.320 ;
      RECT 0.168 97.656 193.369 97.704 ;
      RECT 0.168 98.040 193.369 98.088 ;
      RECT 0.168 98.424 193.369 98.472 ;
      RECT 0.168 98.808 193.369 98.856 ;
      RECT 0.168 99.192 193.369 99.240 ;
      RECT 0.168 99.576 193.369 99.624 ;
      RECT 0.168 99.960 193.369 100.008 ;
      RECT 0.168 100.344 193.369 100.392 ;
      RECT 0.168 100.728 193.369 100.776 ;
      RECT 0.168 101.112 193.369 101.160 ;
      RECT 0.168 101.496 193.369 101.544 ;
      RECT 0.168 101.880 193.369 101.928 ;
      RECT 0.168 102.264 193.369 102.312 ;
      RECT 0.168 102.648 193.369 102.696 ;
      RECT 0.168 103.032 193.369 103.080 ;
      RECT 0.168 103.416 193.369 103.464 ;
      RECT 0.168 103.800 193.369 103.848 ;
      RECT 0.168 104.184 193.369 104.232 ;
      RECT 0.168 104.568 193.369 104.616 ;
      RECT 0.168 104.952 193.369 105.000 ;
      RECT 0.168 105.336 193.369 105.384 ;
      RECT 0.168 105.720 193.369 105.768 ;
      RECT 0.168 106.104 193.369 106.152 ;
      RECT 0.168 106.488 193.369 106.536 ;
      RECT 0.168 106.872 193.369 106.920 ;
      RECT 0.168 107.256 193.369 107.304 ;
      RECT 0.168 107.640 193.369 107.688 ;
      RECT 0.168 108.024 193.369 108.072 ;
      RECT 0.168 108.408 193.369 108.456 ;
      RECT 0.168 108.792 193.369 108.840 ;
      RECT 0.168 109.176 193.369 109.224 ;
      RECT 0.168 109.560 193.369 109.608 ;
      RECT 0.168 109.944 193.369 109.992 ;
      RECT 0.168 110.328 193.369 110.376 ;
      RECT 0.168 110.712 193.369 110.760 ;
      RECT 0.168 111.096 193.369 111.144 ;
      RECT 0.168 111.480 193.369 111.528 ;
      RECT 0.168 111.864 193.369 111.912 ;
      RECT 0.168 112.248 193.369 112.296 ;
      RECT 0.168 112.632 193.369 112.680 ;
      RECT 0.168 113.016 193.369 113.064 ;
      RECT 0.168 113.400 193.369 113.448 ;
      RECT 0.168 113.784 193.369 113.832 ;
      RECT 0.168 114.168 193.369 114.216 ;
      RECT 0.168 114.552 193.369 114.600 ;
      RECT 0.168 114.936 193.369 114.984 ;
      RECT 0.168 115.320 193.369 115.368 ;
      RECT 0.168 115.704 193.369 115.752 ;
      RECT 0.168 116.088 193.369 116.136 ;
      RECT 0.168 116.472 193.369 116.520 ;
      RECT 0.168 116.856 193.369 116.904 ;
      RECT 0.168 117.240 193.369 117.288 ;
      RECT 0.168 117.624 193.369 117.672 ;
      RECT 0.168 118.008 193.369 118.056 ;
      RECT 0.168 118.392 193.369 118.440 ;
      RECT 0.168 118.776 193.369 118.824 ;
      RECT 0.168 119.160 193.369 119.208 ;
      RECT 0.168 119.544 193.369 119.592 ;
      RECT 0.168 119.928 193.369 119.976 ;
      RECT 0.168 120.312 193.369 120.360 ;
      RECT 0.168 120.696 193.369 120.744 ;
      RECT 0.168 121.080 193.369 121.128 ;
      RECT 0.168 121.464 193.369 121.512 ;
      RECT 0.168 121.848 193.369 121.896 ;
      RECT 0.168 122.232 193.369 122.280 ;
      RECT 0.168 122.616 193.369 122.664 ;
      RECT 0.168 123.000 193.369 123.048 ;
      RECT 0.168 123.384 193.369 123.432 ;
      RECT 0.168 123.768 193.369 123.816 ;
      RECT 0.168 124.152 193.369 124.200 ;
      RECT 0.168 124.536 193.369 124.584 ;
      RECT 0.168 124.920 193.369 124.968 ;
      RECT 0.168 125.304 193.369 125.352 ;
      RECT 0.168 125.688 193.369 125.736 ;
      RECT 0.168 126.072 193.369 126.120 ;
      RECT 0.168 126.456 193.369 126.504 ;
      RECT 0.168 126.840 193.369 126.888 ;
      RECT 0.168 127.224 193.369 127.272 ;
      RECT 0.168 127.608 193.369 127.656 ;
      RECT 0.168 127.992 193.369 128.040 ;
      RECT 0.168 128.376 193.369 128.424 ;
      RECT 0.168 128.760 193.369 128.808 ;
      RECT 0.168 129.144 193.369 129.192 ;
      RECT 0.168 129.528 193.369 129.576 ;
      RECT 0.168 129.912 193.369 129.960 ;
      RECT 0.168 130.296 193.369 130.344 ;
      RECT 0.168 130.680 193.369 130.728 ;
      RECT 0.168 131.064 193.369 131.112 ;
      RECT 0.168 131.448 193.369 131.496 ;
      RECT 0.168 131.832 193.369 131.880 ;
      RECT 0.168 132.216 193.369 132.264 ;
      RECT 0.168 132.600 193.369 132.648 ;
      RECT 0.168 132.984 193.369 133.032 ;
      RECT 0.168 133.368 193.369 133.416 ;
      RECT 0.168 133.752 193.369 133.800 ;
      RECT 0.168 134.136 193.369 134.184 ;
      RECT 0.168 134.520 193.369 134.568 ;
      RECT 0.168 134.904 193.369 134.952 ;
      RECT 0.168 135.288 193.369 135.336 ;
      RECT 0.168 135.672 193.369 135.720 ;
      RECT 0.168 136.056 193.369 136.104 ;
      RECT 0.168 136.440 193.369 136.488 ;
      RECT 0.168 136.824 193.369 136.872 ;
      RECT 0.168 137.208 193.369 137.256 ;
      RECT 0.168 137.592 193.369 137.640 ;
      RECT 0.168 137.976 193.369 138.024 ;
      RECT 0.168 138.360 193.369 138.408 ;
      RECT 0.168 138.744 193.369 138.792 ;
      RECT 0.168 139.128 193.369 139.176 ;
      RECT 0.168 139.512 193.369 139.560 ;
      RECT 0.168 139.896 193.369 139.944 ;
      RECT 0.168 140.280 193.369 140.328 ;
      RECT 0.168 140.664 193.369 140.712 ;
      RECT 0.168 141.048 193.369 141.096 ;
      RECT 0.168 141.432 193.369 141.480 ;
      RECT 0.168 141.816 193.369 141.864 ;
      RECT 0.168 142.200 193.369 142.248 ;
      RECT 0.168 142.584 193.369 142.632 ;
      RECT 0.168 142.968 193.369 143.016 ;
      RECT 0.168 143.352 193.369 143.400 ;
      RECT 0.168 143.736 193.369 143.784 ;
      RECT 0.168 144.120 193.369 144.168 ;
      RECT 0.168 144.504 193.369 144.552 ;
      RECT 0.168 144.888 193.369 144.936 ;
      RECT 0.168 145.272 193.369 145.320 ;
      RECT 0.168 145.656 193.369 145.704 ;
      RECT 0.168 146.040 193.369 146.088 ;
      RECT 0.168 146.424 193.369 146.472 ;
      RECT 0.168 146.808 193.369 146.856 ;
      RECT 0.168 147.192 193.369 147.240 ;
      RECT 0.168 147.576 193.369 147.624 ;
      RECT 0.168 147.960 193.369 148.008 ;
      RECT 0.168 148.344 193.369 148.392 ;
      RECT 0.168 148.728 193.369 148.776 ;
      RECT 0.168 149.112 193.369 149.160 ;
      RECT 0.168 149.496 193.369 149.544 ;
      RECT 0.168 149.880 193.369 149.928 ;
      RECT 0.168 150.264 193.369 150.312 ;
      RECT 0.168 150.648 193.369 150.696 ;
      RECT 0.168 151.032 193.369 151.080 ;
      RECT 0.168 151.416 193.369 151.464 ;
      RECT 0.168 151.800 193.369 151.848 ;
      RECT 0.168 152.184 193.369 152.232 ;
      RECT 0.168 152.568 193.369 152.616 ;
      RECT 0.168 152.952 193.369 153.000 ;
      RECT 0.168 153.336 193.369 153.384 ;
      RECT 0.168 153.720 193.369 153.768 ;
      RECT 0.168 154.104 193.369 154.152 ;
      RECT 0.168 154.488 193.369 154.536 ;
      RECT 0.168 154.872 193.369 154.920 ;
      RECT 0.168 155.256 193.369 155.304 ;
      RECT 0.168 155.640 193.369 155.688 ;
      RECT 0.168 156.024 193.369 156.072 ;
      RECT 0.168 156.408 193.369 156.456 ;
      RECT 0.168 156.792 193.369 156.840 ;
      RECT 0.168 157.176 193.369 157.224 ;
      RECT 0.168 157.560 193.369 157.608 ;
      RECT 0.168 157.944 193.369 157.992 ;
      RECT 0.168 158.328 193.369 158.376 ;
      RECT 0.168 158.712 193.369 158.760 ;
      RECT 0.168 159.096 193.369 159.144 ;
      RECT 0.168 159.480 193.369 159.528 ;
      RECT 0.168 159.864 193.369 159.912 ;
      RECT 0.168 160.248 193.369 160.296 ;
      RECT 0.168 160.632 193.369 160.680 ;
      RECT 0.168 161.016 193.369 161.064 ;
      RECT 0.168 161.400 193.369 161.448 ;
      RECT 0.168 161.784 193.369 161.832 ;
      RECT 0.168 162.168 193.369 162.216 ;
      RECT 0.168 162.552 193.369 162.600 ;
      RECT 0.168 162.936 193.369 162.984 ;
      RECT 0.168 163.320 193.369 163.368 ;
      RECT 0.168 163.704 193.369 163.752 ;
      RECT 0.168 164.088 193.369 164.136 ;
      RECT 0.168 164.472 193.369 164.520 ;
      RECT 0.168 164.856 193.369 164.904 ;
      RECT 0.168 165.240 193.369 165.288 ;
      RECT 0.168 165.624 193.369 165.672 ;
      RECT 0.168 166.008 193.369 166.056 ;
      RECT 0.168 166.392 193.369 166.440 ;
      RECT 0.168 166.776 193.369 166.824 ;
      RECT 0.168 167.160 193.369 167.208 ;
      RECT 0.168 167.544 193.369 167.592 ;
      RECT 0.168 167.928 193.369 167.976 ;
      RECT 0.168 168.312 193.369 168.360 ;
      RECT 0.168 168.696 193.369 168.744 ;
      RECT 0.168 169.080 193.369 169.128 ;
      RECT 0.168 169.464 193.369 169.512 ;
      RECT 0.168 169.848 193.369 169.896 ;
      RECT 0.168 170.232 193.369 170.280 ;
      RECT 0.168 170.616 193.369 170.664 ;
      RECT 0.168 171.000 193.369 171.048 ;
      RECT 0.168 171.384 193.369 171.432 ;
      RECT 0.168 171.768 193.369 171.816 ;
      RECT 0.168 172.152 193.369 172.200 ;
      RECT 0.168 172.536 193.369 172.584 ;
      RECT 0.168 172.920 193.369 172.968 ;
      RECT 0.168 173.304 193.369 173.352 ;
      RECT 0.168 173.688 193.369 173.736 ;
      RECT 0.168 174.072 193.369 174.120 ;
      RECT 0.168 174.456 193.369 174.504 ;
      RECT 0.168 174.840 193.369 174.888 ;
      RECT 0.168 175.224 193.369 175.272 ;
      RECT 0.168 175.608 193.369 175.656 ;
      RECT 0.168 175.992 193.369 176.040 ;
      RECT 0.168 176.376 193.369 176.424 ;
      RECT 0.168 176.760 193.369 176.808 ;
      RECT 0.168 177.144 193.369 177.192 ;
      RECT 0.168 177.528 193.369 177.576 ;
      RECT 0.168 177.912 193.369 177.960 ;
      RECT 0.168 178.296 193.369 178.344 ;
      RECT 0.168 178.680 193.369 178.728 ;
      RECT 0.168 179.064 193.369 179.112 ;
      RECT 0.168 179.448 193.369 179.496 ;
      RECT 0.168 179.832 193.369 179.880 ;
      RECT 0.168 180.216 193.369 180.264 ;
      RECT 0.168 180.600 193.369 180.648 ;
      RECT 0.168 180.984 193.369 181.032 ;
      RECT 0.168 181.368 193.369 181.416 ;
      RECT 0.168 181.752 193.369 181.800 ;
      RECT 0.168 182.136 193.369 182.184 ;
      RECT 0.168 182.520 193.369 182.568 ;
      RECT 0.168 182.904 193.369 182.952 ;
      RECT 0.168 183.288 193.369 183.336 ;
      RECT 0.168 183.672 193.369 183.720 ;
      RECT 0.168 184.056 193.369 184.104 ;
      RECT 0.168 184.440 193.369 184.488 ;
      RECT 0.168 184.824 193.369 184.872 ;
      RECT 0.168 185.208 193.369 185.256 ;
      RECT 0.168 185.592 193.369 185.640 ;
      RECT 0.168 185.976 193.369 186.024 ;
      RECT 0.168 186.360 193.369 186.408 ;
      RECT 0.168 186.744 193.369 186.792 ;
      RECT 0.168 187.128 193.369 187.176 ;
      RECT 0.168 187.512 193.369 187.560 ;
      RECT 0.168 187.896 193.369 187.944 ;
      RECT 0.168 188.280 193.369 188.328 ;
      RECT 0.168 188.664 193.369 188.712 ;
      RECT 0.168 189.048 193.369 189.096 ;
      RECT 0.168 189.432 193.369 189.480 ;
      RECT 0.168 189.816 193.369 189.864 ;
      RECT 0.168 190.200 193.369 190.248 ;
      RECT 0.168 190.584 193.369 190.632 ;
      RECT 0.168 190.968 193.369 191.016 ;
      RECT 0.168 191.352 193.369 191.400 ;
      RECT 0.168 191.736 193.369 191.784 ;
      RECT 0.168 192.120 193.369 192.168 ;
      RECT 0.168 192.504 193.369 192.552 ;
      RECT 0.168 192.888 193.369 192.936 ;
      RECT 0.168 193.272 193.369 193.320 ;
      RECT 0.168 193.656 193.369 193.704 ;
      RECT 0.168 194.040 193.369 194.088 ;
      RECT 0.168 194.424 193.369 194.472 ;
      RECT 0.168 194.808 193.369 194.856 ;
      RECT 0.168 195.192 193.369 195.240 ;
      RECT 0.168 195.576 193.369 195.624 ;
      RECT 0.168 195.960 193.369 196.008 ;
      RECT 0.168 196.344 193.369 196.392 ;
      RECT 0.168 196.728 193.369 196.776 ;
      RECT 0.168 197.112 193.369 197.160 ;
      RECT 0.168 197.496 193.369 197.544 ;
      RECT 0.168 197.880 193.369 197.928 ;
      RECT 0.168 198.264 193.369 198.312 ;
      RECT 0.168 198.648 193.369 198.696 ;
      RECT 0.168 199.032 193.369 199.080 ;
      RECT 0.168 199.416 193.369 199.464 ;
      RECT 0.168 199.800 193.369 199.848 ;
      RECT 0.168 200.184 193.369 200.232 ;
      RECT 0.168 200.568 193.369 200.616 ;
      RECT 0.168 200.952 193.369 201.000 ;
      RECT 0.168 201.336 193.369 201.384 ;
      RECT 0.168 201.720 193.369 201.768 ;
      RECT 0.168 202.104 193.369 202.152 ;
      RECT 0.168 202.488 193.369 202.536 ;
      RECT 0.168 202.872 193.369 202.920 ;
      RECT 0.168 203.256 193.369 203.304 ;
      RECT 0.168 203.640 193.369 203.688 ;
      RECT 0.168 204.024 193.369 204.072 ;
      RECT 0.168 204.408 193.369 204.456 ;
      RECT 0.168 204.792 193.369 204.840 ;
      RECT 0.168 205.176 193.369 205.224 ;
      RECT 0.168 205.560 193.369 205.608 ;
      RECT 0.168 205.944 193.369 205.992 ;
      RECT 0.168 206.328 193.369 206.376 ;
      RECT 0.168 206.712 193.369 206.760 ;
      RECT 0.168 207.096 193.369 207.144 ;
      RECT 0.168 207.480 193.369 207.528 ;
      RECT 0.168 207.864 193.369 207.912 ;
      RECT 0.168 208.248 193.369 208.296 ;
      RECT 0.168 208.632 193.369 208.680 ;
      RECT 0.168 209.016 193.369 209.064 ;
      RECT 0.168 209.400 193.369 209.448 ;
      RECT 0.168 209.784 193.369 209.832 ;
      RECT 0.168 210.168 193.369 210.216 ;
      RECT 0.168 210.552 193.369 210.600 ;
      RECT 0.168 210.936 193.369 210.984 ;
      RECT 0.168 211.320 193.369 211.368 ;
      RECT 0.168 211.704 193.369 211.752 ;
      RECT 0.168 212.088 193.369 212.136 ;
      RECT 0.168 212.472 193.369 212.520 ;
      RECT 0.168 212.856 193.369 212.904 ;
      RECT 0.168 213.240 193.369 213.288 ;
      RECT 0.168 213.624 193.369 213.672 ;
      RECT 0.168 214.008 193.369 214.056 ;
      RECT 0.168 214.392 193.369 214.440 ;
      RECT 0.168 214.776 193.369 214.824 ;
      RECT 0.168 215.160 193.369 215.208 ;
      RECT 0.168 215.544 193.369 215.592 ;
      RECT 0.168 215.928 193.369 215.976 ;
      RECT 0.168 216.312 193.369 216.360 ;
      RECT 0.168 216.696 193.369 216.744 ;
      RECT 0.168 217.080 193.369 217.128 ;
      RECT 0.168 217.464 193.369 217.512 ;
      RECT 0.168 217.848 193.369 217.896 ;
      RECT 0.168 218.232 193.369 218.280 ;
      RECT 0.168 218.616 193.369 218.664 ;
      RECT 0.168 219.000 193.369 219.048 ;
      RECT 0.168 219.384 193.369 219.432 ;
      RECT 0.168 219.768 193.369 219.816 ;
      RECT 0.168 220.152 193.369 220.200 ;
      RECT 0.168 220.536 193.369 220.584 ;
      RECT 0.168 220.920 193.369 220.968 ;
      RECT 0.168 221.304 193.369 221.352 ;
      RECT 0.168 221.688 193.369 221.736 ;
      RECT 0.168 222.072 193.369 222.120 ;
      RECT 0.168 222.456 193.369 222.504 ;
      RECT 0.168 222.840 193.369 222.888 ;
      RECT 0.168 223.224 193.369 223.272 ;
      RECT 0.168 223.608 193.369 223.656 ;
      RECT 0.168 223.992 193.369 224.040 ;
      RECT 0.168 224.376 193.369 224.424 ;
      RECT 0.168 224.760 193.369 224.808 ;
      RECT 0.168 225.144 193.369 225.192 ;
      RECT 0.168 225.528 193.369 225.576 ;
      RECT 0.168 225.912 193.369 225.960 ;
      RECT 0.168 226.296 193.369 226.344 ;
      RECT 0.168 226.680 193.369 226.728 ;
      RECT 0.168 227.064 193.369 227.112 ;
      RECT 0.168 227.448 193.369 227.496 ;
      RECT 0.168 227.832 193.369 227.880 ;
      RECT 0.168 228.216 193.369 228.264 ;
      RECT 0.168 228.600 193.369 228.648 ;
      RECT 0.168 228.984 193.369 229.032 ;
      RECT 0.168 229.368 193.369 229.416 ;
      RECT 0.168 229.752 193.369 229.800 ;
      RECT 0.168 230.136 193.369 230.184 ;
      RECT 0.168 230.520 193.369 230.568 ;
      RECT 0.168 230.904 193.369 230.952 ;
      RECT 0.168 231.288 193.369 231.336 ;
      RECT 0.168 231.672 193.369 231.720 ;
      RECT 0.168 232.056 193.369 232.104 ;
      RECT 0.168 232.440 193.369 232.488 ;
      RECT 0.168 232.824 193.369 232.872 ;
      RECT 0.168 233.208 193.369 233.256 ;
      RECT 0.168 233.592 193.369 233.640 ;
      RECT 0.168 233.976 193.369 234.024 ;
      RECT 0.168 234.360 193.369 234.408 ;
      RECT 0.168 234.744 193.369 234.792 ;
      RECT 0.168 235.128 193.369 235.176 ;
      RECT 0.168 235.512 193.369 235.560 ;
      RECT 0.168 235.896 193.369 235.944 ;
      RECT 0.168 236.280 193.369 236.328 ;
      RECT 0.168 236.664 193.369 236.712 ;
      RECT 0.168 237.048 193.369 237.096 ;
      RECT 0.168 237.432 193.369 237.480 ;
      RECT 0.168 237.816 193.369 237.864 ;
      RECT 0.168 238.200 193.369 238.248 ;
      RECT 0.168 238.584 193.369 238.632 ;
      RECT 0.168 238.968 193.369 239.016 ;
      RECT 0.168 239.352 193.369 239.400 ;
      RECT 0.168 239.736 193.369 239.784 ;
      RECT 0.168 240.120 193.369 240.168 ;
      RECT 0.168 240.504 193.369 240.552 ;
      RECT 0.168 240.888 193.369 240.936 ;
      RECT 0.168 241.272 193.369 241.320 ;
      RECT 0.168 241.656 193.369 241.704 ;
      RECT 0.168 242.040 193.369 242.088 ;
      RECT 0.168 242.424 193.369 242.472 ;
      RECT 0.168 242.808 193.369 242.856 ;
      RECT 0.168 243.192 193.369 243.240 ;
      RECT 0.168 243.576 193.369 243.624 ;
      RECT 0.168 243.960 193.369 244.008 ;
      RECT 0.168 244.344 193.369 244.392 ;
      RECT 0.168 244.728 193.369 244.776 ;
      RECT 0.168 245.112 193.369 245.160 ;
      RECT 0.168 245.496 193.369 245.544 ;
      RECT 0.168 245.880 193.369 245.928 ;
      RECT 0.168 246.264 193.369 246.312 ;
      RECT 0.168 246.648 193.369 246.696 ;
      RECT 0.168 247.032 193.369 247.080 ;
      RECT 0.168 247.416 193.369 247.464 ;
      RECT 0.168 247.800 193.369 247.848 ;
      RECT 0.168 248.184 193.369 248.232 ;
      RECT 0.168 248.568 193.369 248.616 ;
      RECT 0.168 248.952 193.369 249.000 ;
      RECT 0.168 249.336 193.369 249.384 ;
      RECT 0.168 249.720 193.369 249.768 ;
      RECT 0.168 250.104 193.369 250.152 ;
      RECT 0.168 250.488 193.369 250.536 ;
      RECT 0.168 250.872 193.369 250.920 ;
      RECT 0.168 251.256 193.369 251.304 ;
      RECT 0.168 251.640 193.369 251.688 ;
      RECT 0.168 252.024 193.369 252.072 ;
      RECT 0.168 252.408 193.369 252.456 ;
      RECT 0.168 252.792 193.369 252.840 ;
      RECT 0.168 253.176 193.369 253.224 ;
      RECT 0.168 253.560 193.369 253.608 ;
      RECT 0.168 253.944 193.369 253.992 ;
      RECT 0.168 254.328 193.369 254.376 ;
      RECT 0.168 254.712 193.369 254.760 ;
      RECT 0.168 255.096 193.369 255.144 ;
      RECT 0.168 255.480 193.369 255.528 ;
      RECT 0.168 255.864 193.369 255.912 ;
      RECT 0.168 256.248 193.369 256.296 ;
      RECT 0.168 256.632 193.369 256.680 ;
      RECT 0.168 257.016 193.369 257.064 ;
      RECT 0.168 257.400 193.369 257.448 ;
      RECT 0.168 257.784 193.369 257.832 ;
      RECT 0.168 258.168 193.369 258.216 ;
      RECT 0.168 258.552 193.369 258.600 ;
      RECT 0.168 258.936 193.369 258.984 ;
      RECT 0.168 259.320 193.369 259.368 ;
      RECT 0.168 259.704 193.369 259.752 ;
      RECT 0.168 260.088 193.369 260.136 ;
      RECT 0.168 260.472 193.369 260.520 ;
      RECT 0.168 260.856 193.369 260.904 ;
      RECT 0.168 261.240 193.369 261.288 ;
      RECT 0.168 261.624 193.369 261.672 ;
      RECT 0.168 262.008 193.369 262.056 ;
      RECT 0.168 262.392 193.369 262.440 ;
      RECT 0.168 262.776 193.369 262.824 ;
      RECT 0.168 263.160 193.369 263.208 ;
      RECT 0.168 263.544 193.369 263.592 ;
      RECT 0.168 263.928 193.369 263.976 ;
      RECT 0.168 264.312 193.369 264.360 ;
      RECT 0.168 264.696 193.369 264.744 ;
      RECT 0.168 265.080 193.369 265.128 ;
      RECT 0.168 265.464 193.369 265.512 ;
      RECT 0.168 265.848 193.369 265.896 ;
      RECT 0.168 266.232 193.369 266.280 ;
      RECT 0.168 266.616 193.369 266.664 ;
      RECT 0.168 267.000 193.369 267.048 ;
      RECT 0.168 267.384 193.369 267.432 ;
      RECT 0.168 267.768 193.369 267.816 ;
      RECT 0.168 268.152 193.369 268.200 ;
      RECT 0.168 268.536 193.369 268.584 ;
      RECT 0.168 268.920 193.369 268.968 ;
      RECT 0.168 269.304 193.369 269.352 ;
      RECT 0.168 269.688 193.369 269.736 ;
      RECT 0.168 270.072 193.369 270.120 ;
      RECT 0.168 270.456 193.369 270.504 ;
      RECT 0.168 270.840 193.369 270.888 ;
      RECT 0.168 271.224 193.369 271.272 ;
      RECT 0.168 271.608 193.369 271.656 ;
      RECT 0.168 271.992 193.369 272.040 ;
      RECT 0.168 272.376 193.369 272.424 ;
      RECT 0.168 272.760 193.369 272.808 ;
      RECT 0.168 273.144 193.369 273.192 ;
      RECT 0.168 273.528 193.369 273.576 ;
      RECT 0.168 273.912 193.369 273.960 ;
      RECT 0.168 274.296 193.369 274.344 ;
      RECT 0.168 274.680 193.369 274.728 ;
      RECT 0.168 275.064 193.369 275.112 ;
      RECT 0.168 275.448 193.369 275.496 ;
      RECT 0.168 275.832 193.369 275.880 ;
      RECT 0.168 276.216 193.369 276.264 ;
      RECT 0.168 276.600 193.369 276.648 ;
      RECT 0.168 276.984 193.369 277.032 ;
      RECT 0.168 277.368 193.369 277.416 ;
      RECT 0.168 277.752 193.369 277.800 ;
      RECT 0.168 278.136 193.369 278.184 ;
      RECT 0.168 278.520 193.369 278.568 ;
      RECT 0.168 278.904 193.369 278.952 ;
      RECT 0.168 279.288 193.369 279.336 ;
      RECT 0.168 279.672 193.369 279.720 ;
      RECT 0.168 280.056 193.369 280.104 ;
      RECT 0.168 280.440 193.369 280.488 ;
      RECT 0.168 280.824 193.369 280.872 ;
      RECT 0.168 281.208 193.369 281.256 ;
      RECT 0.168 281.592 193.369 281.640 ;
      RECT 0.168 281.976 193.369 282.024 ;
      RECT 0.168 282.360 193.369 282.408 ;
      RECT 0.168 282.744 193.369 282.792 ;
      RECT 0.168 283.128 193.369 283.176 ;
      RECT 0.168 283.512 193.369 283.560 ;
      RECT 0.168 283.896 193.369 283.944 ;
      RECT 0.168 284.280 193.369 284.328 ;
      RECT 0.168 284.664 193.369 284.712 ;
      RECT 0.168 285.048 193.369 285.096 ;
      RECT 0.168 285.432 193.369 285.480 ;
      RECT 0.168 285.816 193.369 285.864 ;
      RECT 0.168 286.200 193.369 286.248 ;
      RECT 0.168 286.584 193.369 286.632 ;
      RECT 0.168 286.968 193.369 287.016 ;
      RECT 0.168 287.352 193.369 287.400 ;
      RECT 0.168 287.736 193.369 287.784 ;
      RECT 0.168 288.120 193.369 288.168 ;
      RECT 0.168 288.504 193.369 288.552 ;
      RECT 0.168 288.888 193.369 288.936 ;
      RECT 0.168 289.272 193.369 289.320 ;
      RECT 0.168 289.656 193.369 289.704 ;
      RECT 0.168 290.040 193.369 290.088 ;
      RECT 0.168 290.424 193.369 290.472 ;
      RECT 0.168 290.808 193.369 290.856 ;
      RECT 0.168 291.192 193.369 291.240 ;
      RECT 0.168 291.576 193.369 291.624 ;
      RECT 0.168 291.960 193.369 292.008 ;
      RECT 0.168 292.344 193.369 292.392 ;
      RECT 0.168 292.728 193.369 292.776 ;
      RECT 0.168 293.112 193.369 293.160 ;
      RECT 0.168 293.496 193.369 293.544 ;
      RECT 0.168 293.880 193.369 293.928 ;
      RECT 0.168 294.264 193.369 294.312 ;
      RECT 0.168 294.648 193.369 294.696 ;
      RECT 0.168 295.032 193.369 295.080 ;
      RECT 0.168 295.416 193.369 295.464 ;
      RECT 0.168 295.800 193.369 295.848 ;
      RECT 0.168 296.184 193.369 296.232 ;
      RECT 0.168 296.568 193.369 296.616 ;
      RECT 0.168 296.952 193.369 297.000 ;
      RECT 0.168 297.336 193.369 297.384 ;
      RECT 0.168 297.720 193.369 297.768 ;
      RECT 0.168 298.104 193.369 298.152 ;
      RECT 0.168 298.488 193.369 298.536 ;
      RECT 0.168 298.872 193.369 298.920 ;
      RECT 0.168 299.256 193.369 299.304 ;
      RECT 0.168 299.640 193.369 299.688 ;
      RECT 0.168 300.024 193.369 300.072 ;
      RECT 0.168 300.408 193.369 300.456 ;
      RECT 0.168 300.792 193.369 300.840 ;
      RECT 0.168 301.176 193.369 301.224 ;
      RECT 0.168 301.560 193.369 301.608 ;
      RECT 0.168 301.944 193.369 301.992 ;
      RECT 0.168 302.328 193.369 302.376 ;
      RECT 0.168 302.712 193.369 302.760 ;
      RECT 0.168 303.096 193.369 303.144 ;
      RECT 0.168 303.480 193.369 303.528 ;
      RECT 0.168 303.864 193.369 303.912 ;
      RECT 0.168 304.248 193.369 304.296 ;
      RECT 0.168 304.632 193.369 304.680 ;
      RECT 0.168 305.016 193.369 305.064 ;
      RECT 0.168 305.400 193.369 305.448 ;
      RECT 0.168 305.784 193.369 305.832 ;
      RECT 0.168 306.168 193.369 306.216 ;
      RECT 0.168 306.552 193.369 306.600 ;
      RECT 0.168 306.936 193.369 306.984 ;
      RECT 0.168 307.320 193.369 307.368 ;
      RECT 0.168 307.704 193.369 307.752 ;
      RECT 0.168 308.088 193.369 308.136 ;
      RECT 0.168 308.472 193.369 308.520 ;
      RECT 0.168 308.856 193.369 308.904 ;
      RECT 0.168 309.240 193.369 309.288 ;
      RECT 0.168 309.624 193.369 309.672 ;
      RECT 0.168 310.008 193.369 310.056 ;
      RECT 0.168 310.392 193.369 310.440 ;
      RECT 0.168 310.776 193.369 310.824 ;
      RECT 0.168 311.160 193.369 311.208 ;
      RECT 0.168 311.544 193.369 311.592 ;
      RECT 0.168 311.928 193.369 311.976 ;
      RECT 0.168 312.312 193.369 312.360 ;
      RECT 0.168 312.696 193.369 312.744 ;
      RECT 0.168 313.080 193.369 313.128 ;
      RECT 0.168 313.464 193.369 313.512 ;
      RECT 0.168 313.848 193.369 313.896 ;
      RECT 0.168 314.232 193.369 314.280 ;
      RECT 0.168 314.616 193.369 314.664 ;
      RECT 0.168 315.000 193.369 315.048 ;
      RECT 0.168 315.384 193.369 315.432 ;
      RECT 0.168 315.768 193.369 315.816 ;
      RECT 0.168 316.152 193.369 316.200 ;
      RECT 0.168 316.536 193.369 316.584 ;
      RECT 0.168 316.920 193.369 316.968 ;
      RECT 0.168 317.304 193.369 317.352 ;
      RECT 0.168 317.688 193.369 317.736 ;
      RECT 0.168 318.072 193.369 318.120 ;
      RECT 0.168 318.456 193.369 318.504 ;
      RECT 0.168 318.840 193.369 318.888 ;
      RECT 0.168 319.224 193.369 319.272 ;
      RECT 0.168 319.608 193.369 319.656 ;
      RECT 0.168 319.992 193.369 320.040 ;
      RECT 0.168 320.376 193.369 320.424 ;
      RECT 0.168 320.760 193.369 320.808 ;
      RECT 0.168 321.144 193.369 321.192 ;
      RECT 0.168 321.528 193.369 321.576 ;
      RECT 0.168 321.912 193.369 321.960 ;
      RECT 0.168 322.296 193.369 322.344 ;
      RECT 0.168 322.680 193.369 322.728 ;
      RECT 0.168 323.064 193.369 323.112 ;
      RECT 0.168 323.448 193.369 323.496 ;
      RECT 0.168 323.832 193.369 323.880 ;
      RECT 0.168 324.216 193.369 324.264 ;
      RECT 0.168 324.600 193.369 324.648 ;
      RECT 0.168 324.984 193.369 325.032 ;
      RECT 0.168 325.368 193.369 325.416 ;
      RECT 0.168 325.752 193.369 325.800 ;
      RECT 0.168 326.136 193.369 326.184 ;
      RECT 0.168 326.520 193.369 326.568 ;
      RECT 0.168 326.904 193.369 326.952 ;
      RECT 0.168 327.288 193.369 327.336 ;
      RECT 0.168 327.672 193.369 327.720 ;
      RECT 0.168 328.056 193.369 328.104 ;
      RECT 0.168 328.440 193.369 328.488 ;
      RECT 0.168 328.824 193.369 328.872 ;
      RECT 0.168 329.208 193.369 329.256 ;
      RECT 0.168 329.592 193.369 329.640 ;
      RECT 0.168 329.976 193.369 330.024 ;
      RECT 0.168 330.360 193.369 330.408 ;
      RECT 0.168 330.744 193.369 330.792 ;
      RECT 0.168 331.128 193.369 331.176 ;
      RECT 0.168 331.512 193.369 331.560 ;
    END
  END VSS
  PIN VDD
    DIRECTION INOUT ;
    USE POWER ;
    PORT
      LAYER M4 ;
      RECT 0.168 0.120 193.369 0.168 ;
      RECT 0.168 0.504 193.369 0.552 ;
      RECT 0.168 0.888 193.369 0.936 ;
      RECT 0.168 1.272 193.369 1.320 ;
      RECT 0.168 1.656 193.369 1.704 ;
      RECT 0.168 2.040 193.369 2.088 ;
      RECT 0.168 2.424 193.369 2.472 ;
      RECT 0.168 2.808 193.369 2.856 ;
      RECT 0.168 3.192 193.369 3.240 ;
      RECT 0.168 3.576 193.369 3.624 ;
      RECT 0.168 3.960 193.369 4.008 ;
      RECT 0.168 4.344 193.369 4.392 ;
      RECT 0.168 4.728 193.369 4.776 ;
      RECT 0.168 5.112 193.369 5.160 ;
      RECT 0.168 5.496 193.369 5.544 ;
      RECT 0.168 5.880 193.369 5.928 ;
      RECT 0.168 6.264 193.369 6.312 ;
      RECT 0.168 6.648 193.369 6.696 ;
      RECT 0.168 7.032 193.369 7.080 ;
      RECT 0.168 7.416 193.369 7.464 ;
      RECT 0.168 7.800 193.369 7.848 ;
      RECT 0.168 8.184 193.369 8.232 ;
      RECT 0.168 8.568 193.369 8.616 ;
      RECT 0.168 8.952 193.369 9.000 ;
      RECT 0.168 9.336 193.369 9.384 ;
      RECT 0.168 9.720 193.369 9.768 ;
      RECT 0.168 10.104 193.369 10.152 ;
      RECT 0.168 10.488 193.369 10.536 ;
      RECT 0.168 10.872 193.369 10.920 ;
      RECT 0.168 11.256 193.369 11.304 ;
      RECT 0.168 11.640 193.369 11.688 ;
      RECT 0.168 12.024 193.369 12.072 ;
      RECT 0.168 12.408 193.369 12.456 ;
      RECT 0.168 12.792 193.369 12.840 ;
      RECT 0.168 13.176 193.369 13.224 ;
      RECT 0.168 13.560 193.369 13.608 ;
      RECT 0.168 13.944 193.369 13.992 ;
      RECT 0.168 14.328 193.369 14.376 ;
      RECT 0.168 14.712 193.369 14.760 ;
      RECT 0.168 15.096 193.369 15.144 ;
      RECT 0.168 15.480 193.369 15.528 ;
      RECT 0.168 15.864 193.369 15.912 ;
      RECT 0.168 16.248 193.369 16.296 ;
      RECT 0.168 16.632 193.369 16.680 ;
      RECT 0.168 17.016 193.369 17.064 ;
      RECT 0.168 17.400 193.369 17.448 ;
      RECT 0.168 17.784 193.369 17.832 ;
      RECT 0.168 18.168 193.369 18.216 ;
      RECT 0.168 18.552 193.369 18.600 ;
      RECT 0.168 18.936 193.369 18.984 ;
      RECT 0.168 19.320 193.369 19.368 ;
      RECT 0.168 19.704 193.369 19.752 ;
      RECT 0.168 20.088 193.369 20.136 ;
      RECT 0.168 20.472 193.369 20.520 ;
      RECT 0.168 20.856 193.369 20.904 ;
      RECT 0.168 21.240 193.369 21.288 ;
      RECT 0.168 21.624 193.369 21.672 ;
      RECT 0.168 22.008 193.369 22.056 ;
      RECT 0.168 22.392 193.369 22.440 ;
      RECT 0.168 22.776 193.369 22.824 ;
      RECT 0.168 23.160 193.369 23.208 ;
      RECT 0.168 23.544 193.369 23.592 ;
      RECT 0.168 23.928 193.369 23.976 ;
      RECT 0.168 24.312 193.369 24.360 ;
      RECT 0.168 24.696 193.369 24.744 ;
      RECT 0.168 25.080 193.369 25.128 ;
      RECT 0.168 25.464 193.369 25.512 ;
      RECT 0.168 25.848 193.369 25.896 ;
      RECT 0.168 26.232 193.369 26.280 ;
      RECT 0.168 26.616 193.369 26.664 ;
      RECT 0.168 27.000 193.369 27.048 ;
      RECT 0.168 27.384 193.369 27.432 ;
      RECT 0.168 27.768 193.369 27.816 ;
      RECT 0.168 28.152 193.369 28.200 ;
      RECT 0.168 28.536 193.369 28.584 ;
      RECT 0.168 28.920 193.369 28.968 ;
      RECT 0.168 29.304 193.369 29.352 ;
      RECT 0.168 29.688 193.369 29.736 ;
      RECT 0.168 30.072 193.369 30.120 ;
      RECT 0.168 30.456 193.369 30.504 ;
      RECT 0.168 30.840 193.369 30.888 ;
      RECT 0.168 31.224 193.369 31.272 ;
      RECT 0.168 31.608 193.369 31.656 ;
      RECT 0.168 31.992 193.369 32.040 ;
      RECT 0.168 32.376 193.369 32.424 ;
      RECT 0.168 32.760 193.369 32.808 ;
      RECT 0.168 33.144 193.369 33.192 ;
      RECT 0.168 33.528 193.369 33.576 ;
      RECT 0.168 33.912 193.369 33.960 ;
      RECT 0.168 34.296 193.369 34.344 ;
      RECT 0.168 34.680 193.369 34.728 ;
      RECT 0.168 35.064 193.369 35.112 ;
      RECT 0.168 35.448 193.369 35.496 ;
      RECT 0.168 35.832 193.369 35.880 ;
      RECT 0.168 36.216 193.369 36.264 ;
      RECT 0.168 36.600 193.369 36.648 ;
      RECT 0.168 36.984 193.369 37.032 ;
      RECT 0.168 37.368 193.369 37.416 ;
      RECT 0.168 37.752 193.369 37.800 ;
      RECT 0.168 38.136 193.369 38.184 ;
      RECT 0.168 38.520 193.369 38.568 ;
      RECT 0.168 38.904 193.369 38.952 ;
      RECT 0.168 39.288 193.369 39.336 ;
      RECT 0.168 39.672 193.369 39.720 ;
      RECT 0.168 40.056 193.369 40.104 ;
      RECT 0.168 40.440 193.369 40.488 ;
      RECT 0.168 40.824 193.369 40.872 ;
      RECT 0.168 41.208 193.369 41.256 ;
      RECT 0.168 41.592 193.369 41.640 ;
      RECT 0.168 41.976 193.369 42.024 ;
      RECT 0.168 42.360 193.369 42.408 ;
      RECT 0.168 42.744 193.369 42.792 ;
      RECT 0.168 43.128 193.369 43.176 ;
      RECT 0.168 43.512 193.369 43.560 ;
      RECT 0.168 43.896 193.369 43.944 ;
      RECT 0.168 44.280 193.369 44.328 ;
      RECT 0.168 44.664 193.369 44.712 ;
      RECT 0.168 45.048 193.369 45.096 ;
      RECT 0.168 45.432 193.369 45.480 ;
      RECT 0.168 45.816 193.369 45.864 ;
      RECT 0.168 46.200 193.369 46.248 ;
      RECT 0.168 46.584 193.369 46.632 ;
      RECT 0.168 46.968 193.369 47.016 ;
      RECT 0.168 47.352 193.369 47.400 ;
      RECT 0.168 47.736 193.369 47.784 ;
      RECT 0.168 48.120 193.369 48.168 ;
      RECT 0.168 48.504 193.369 48.552 ;
      RECT 0.168 48.888 193.369 48.936 ;
      RECT 0.168 49.272 193.369 49.320 ;
      RECT 0.168 49.656 193.369 49.704 ;
      RECT 0.168 50.040 193.369 50.088 ;
      RECT 0.168 50.424 193.369 50.472 ;
      RECT 0.168 50.808 193.369 50.856 ;
      RECT 0.168 51.192 193.369 51.240 ;
      RECT 0.168 51.576 193.369 51.624 ;
      RECT 0.168 51.960 193.369 52.008 ;
      RECT 0.168 52.344 193.369 52.392 ;
      RECT 0.168 52.728 193.369 52.776 ;
      RECT 0.168 53.112 193.369 53.160 ;
      RECT 0.168 53.496 193.369 53.544 ;
      RECT 0.168 53.880 193.369 53.928 ;
      RECT 0.168 54.264 193.369 54.312 ;
      RECT 0.168 54.648 193.369 54.696 ;
      RECT 0.168 55.032 193.369 55.080 ;
      RECT 0.168 55.416 193.369 55.464 ;
      RECT 0.168 55.800 193.369 55.848 ;
      RECT 0.168 56.184 193.369 56.232 ;
      RECT 0.168 56.568 193.369 56.616 ;
      RECT 0.168 56.952 193.369 57.000 ;
      RECT 0.168 57.336 193.369 57.384 ;
      RECT 0.168 57.720 193.369 57.768 ;
      RECT 0.168 58.104 193.369 58.152 ;
      RECT 0.168 58.488 193.369 58.536 ;
      RECT 0.168 58.872 193.369 58.920 ;
      RECT 0.168 59.256 193.369 59.304 ;
      RECT 0.168 59.640 193.369 59.688 ;
      RECT 0.168 60.024 193.369 60.072 ;
      RECT 0.168 60.408 193.369 60.456 ;
      RECT 0.168 60.792 193.369 60.840 ;
      RECT 0.168 61.176 193.369 61.224 ;
      RECT 0.168 61.560 193.369 61.608 ;
      RECT 0.168 61.944 193.369 61.992 ;
      RECT 0.168 62.328 193.369 62.376 ;
      RECT 0.168 62.712 193.369 62.760 ;
      RECT 0.168 63.096 193.369 63.144 ;
      RECT 0.168 63.480 193.369 63.528 ;
      RECT 0.168 63.864 193.369 63.912 ;
      RECT 0.168 64.248 193.369 64.296 ;
      RECT 0.168 64.632 193.369 64.680 ;
      RECT 0.168 65.016 193.369 65.064 ;
      RECT 0.168 65.400 193.369 65.448 ;
      RECT 0.168 65.784 193.369 65.832 ;
      RECT 0.168 66.168 193.369 66.216 ;
      RECT 0.168 66.552 193.369 66.600 ;
      RECT 0.168 66.936 193.369 66.984 ;
      RECT 0.168 67.320 193.369 67.368 ;
      RECT 0.168 67.704 193.369 67.752 ;
      RECT 0.168 68.088 193.369 68.136 ;
      RECT 0.168 68.472 193.369 68.520 ;
      RECT 0.168 68.856 193.369 68.904 ;
      RECT 0.168 69.240 193.369 69.288 ;
      RECT 0.168 69.624 193.369 69.672 ;
      RECT 0.168 70.008 193.369 70.056 ;
      RECT 0.168 70.392 193.369 70.440 ;
      RECT 0.168 70.776 193.369 70.824 ;
      RECT 0.168 71.160 193.369 71.208 ;
      RECT 0.168 71.544 193.369 71.592 ;
      RECT 0.168 71.928 193.369 71.976 ;
      RECT 0.168 72.312 193.369 72.360 ;
      RECT 0.168 72.696 193.369 72.744 ;
      RECT 0.168 73.080 193.369 73.128 ;
      RECT 0.168 73.464 193.369 73.512 ;
      RECT 0.168 73.848 193.369 73.896 ;
      RECT 0.168 74.232 193.369 74.280 ;
      RECT 0.168 74.616 193.369 74.664 ;
      RECT 0.168 75.000 193.369 75.048 ;
      RECT 0.168 75.384 193.369 75.432 ;
      RECT 0.168 75.768 193.369 75.816 ;
      RECT 0.168 76.152 193.369 76.200 ;
      RECT 0.168 76.536 193.369 76.584 ;
      RECT 0.168 76.920 193.369 76.968 ;
      RECT 0.168 77.304 193.369 77.352 ;
      RECT 0.168 77.688 193.369 77.736 ;
      RECT 0.168 78.072 193.369 78.120 ;
      RECT 0.168 78.456 193.369 78.504 ;
      RECT 0.168 78.840 193.369 78.888 ;
      RECT 0.168 79.224 193.369 79.272 ;
      RECT 0.168 79.608 193.369 79.656 ;
      RECT 0.168 79.992 193.369 80.040 ;
      RECT 0.168 80.376 193.369 80.424 ;
      RECT 0.168 80.760 193.369 80.808 ;
      RECT 0.168 81.144 193.369 81.192 ;
      RECT 0.168 81.528 193.369 81.576 ;
      RECT 0.168 81.912 193.369 81.960 ;
      RECT 0.168 82.296 193.369 82.344 ;
      RECT 0.168 82.680 193.369 82.728 ;
      RECT 0.168 83.064 193.369 83.112 ;
      RECT 0.168 83.448 193.369 83.496 ;
      RECT 0.168 83.832 193.369 83.880 ;
      RECT 0.168 84.216 193.369 84.264 ;
      RECT 0.168 84.600 193.369 84.648 ;
      RECT 0.168 84.984 193.369 85.032 ;
      RECT 0.168 85.368 193.369 85.416 ;
      RECT 0.168 85.752 193.369 85.800 ;
      RECT 0.168 86.136 193.369 86.184 ;
      RECT 0.168 86.520 193.369 86.568 ;
      RECT 0.168 86.904 193.369 86.952 ;
      RECT 0.168 87.288 193.369 87.336 ;
      RECT 0.168 87.672 193.369 87.720 ;
      RECT 0.168 88.056 193.369 88.104 ;
      RECT 0.168 88.440 193.369 88.488 ;
      RECT 0.168 88.824 193.369 88.872 ;
      RECT 0.168 89.208 193.369 89.256 ;
      RECT 0.168 89.592 193.369 89.640 ;
      RECT 0.168 89.976 193.369 90.024 ;
      RECT 0.168 90.360 193.369 90.408 ;
      RECT 0.168 90.744 193.369 90.792 ;
      RECT 0.168 91.128 193.369 91.176 ;
      RECT 0.168 91.512 193.369 91.560 ;
      RECT 0.168 91.896 193.369 91.944 ;
      RECT 0.168 92.280 193.369 92.328 ;
      RECT 0.168 92.664 193.369 92.712 ;
      RECT 0.168 93.048 193.369 93.096 ;
      RECT 0.168 93.432 193.369 93.480 ;
      RECT 0.168 93.816 193.369 93.864 ;
      RECT 0.168 94.200 193.369 94.248 ;
      RECT 0.168 94.584 193.369 94.632 ;
      RECT 0.168 94.968 193.369 95.016 ;
      RECT 0.168 95.352 193.369 95.400 ;
      RECT 0.168 95.736 193.369 95.784 ;
      RECT 0.168 96.120 193.369 96.168 ;
      RECT 0.168 96.504 193.369 96.552 ;
      RECT 0.168 96.888 193.369 96.936 ;
      RECT 0.168 97.272 193.369 97.320 ;
      RECT 0.168 97.656 193.369 97.704 ;
      RECT 0.168 98.040 193.369 98.088 ;
      RECT 0.168 98.424 193.369 98.472 ;
      RECT 0.168 98.808 193.369 98.856 ;
      RECT 0.168 99.192 193.369 99.240 ;
      RECT 0.168 99.576 193.369 99.624 ;
      RECT 0.168 99.960 193.369 100.008 ;
      RECT 0.168 100.344 193.369 100.392 ;
      RECT 0.168 100.728 193.369 100.776 ;
      RECT 0.168 101.112 193.369 101.160 ;
      RECT 0.168 101.496 193.369 101.544 ;
      RECT 0.168 101.880 193.369 101.928 ;
      RECT 0.168 102.264 193.369 102.312 ;
      RECT 0.168 102.648 193.369 102.696 ;
      RECT 0.168 103.032 193.369 103.080 ;
      RECT 0.168 103.416 193.369 103.464 ;
      RECT 0.168 103.800 193.369 103.848 ;
      RECT 0.168 104.184 193.369 104.232 ;
      RECT 0.168 104.568 193.369 104.616 ;
      RECT 0.168 104.952 193.369 105.000 ;
      RECT 0.168 105.336 193.369 105.384 ;
      RECT 0.168 105.720 193.369 105.768 ;
      RECT 0.168 106.104 193.369 106.152 ;
      RECT 0.168 106.488 193.369 106.536 ;
      RECT 0.168 106.872 193.369 106.920 ;
      RECT 0.168 107.256 193.369 107.304 ;
      RECT 0.168 107.640 193.369 107.688 ;
      RECT 0.168 108.024 193.369 108.072 ;
      RECT 0.168 108.408 193.369 108.456 ;
      RECT 0.168 108.792 193.369 108.840 ;
      RECT 0.168 109.176 193.369 109.224 ;
      RECT 0.168 109.560 193.369 109.608 ;
      RECT 0.168 109.944 193.369 109.992 ;
      RECT 0.168 110.328 193.369 110.376 ;
      RECT 0.168 110.712 193.369 110.760 ;
      RECT 0.168 111.096 193.369 111.144 ;
      RECT 0.168 111.480 193.369 111.528 ;
      RECT 0.168 111.864 193.369 111.912 ;
      RECT 0.168 112.248 193.369 112.296 ;
      RECT 0.168 112.632 193.369 112.680 ;
      RECT 0.168 113.016 193.369 113.064 ;
      RECT 0.168 113.400 193.369 113.448 ;
      RECT 0.168 113.784 193.369 113.832 ;
      RECT 0.168 114.168 193.369 114.216 ;
      RECT 0.168 114.552 193.369 114.600 ;
      RECT 0.168 114.936 193.369 114.984 ;
      RECT 0.168 115.320 193.369 115.368 ;
      RECT 0.168 115.704 193.369 115.752 ;
      RECT 0.168 116.088 193.369 116.136 ;
      RECT 0.168 116.472 193.369 116.520 ;
      RECT 0.168 116.856 193.369 116.904 ;
      RECT 0.168 117.240 193.369 117.288 ;
      RECT 0.168 117.624 193.369 117.672 ;
      RECT 0.168 118.008 193.369 118.056 ;
      RECT 0.168 118.392 193.369 118.440 ;
      RECT 0.168 118.776 193.369 118.824 ;
      RECT 0.168 119.160 193.369 119.208 ;
      RECT 0.168 119.544 193.369 119.592 ;
      RECT 0.168 119.928 193.369 119.976 ;
      RECT 0.168 120.312 193.369 120.360 ;
      RECT 0.168 120.696 193.369 120.744 ;
      RECT 0.168 121.080 193.369 121.128 ;
      RECT 0.168 121.464 193.369 121.512 ;
      RECT 0.168 121.848 193.369 121.896 ;
      RECT 0.168 122.232 193.369 122.280 ;
      RECT 0.168 122.616 193.369 122.664 ;
      RECT 0.168 123.000 193.369 123.048 ;
      RECT 0.168 123.384 193.369 123.432 ;
      RECT 0.168 123.768 193.369 123.816 ;
      RECT 0.168 124.152 193.369 124.200 ;
      RECT 0.168 124.536 193.369 124.584 ;
      RECT 0.168 124.920 193.369 124.968 ;
      RECT 0.168 125.304 193.369 125.352 ;
      RECT 0.168 125.688 193.369 125.736 ;
      RECT 0.168 126.072 193.369 126.120 ;
      RECT 0.168 126.456 193.369 126.504 ;
      RECT 0.168 126.840 193.369 126.888 ;
      RECT 0.168 127.224 193.369 127.272 ;
      RECT 0.168 127.608 193.369 127.656 ;
      RECT 0.168 127.992 193.369 128.040 ;
      RECT 0.168 128.376 193.369 128.424 ;
      RECT 0.168 128.760 193.369 128.808 ;
      RECT 0.168 129.144 193.369 129.192 ;
      RECT 0.168 129.528 193.369 129.576 ;
      RECT 0.168 129.912 193.369 129.960 ;
      RECT 0.168 130.296 193.369 130.344 ;
      RECT 0.168 130.680 193.369 130.728 ;
      RECT 0.168 131.064 193.369 131.112 ;
      RECT 0.168 131.448 193.369 131.496 ;
      RECT 0.168 131.832 193.369 131.880 ;
      RECT 0.168 132.216 193.369 132.264 ;
      RECT 0.168 132.600 193.369 132.648 ;
      RECT 0.168 132.984 193.369 133.032 ;
      RECT 0.168 133.368 193.369 133.416 ;
      RECT 0.168 133.752 193.369 133.800 ;
      RECT 0.168 134.136 193.369 134.184 ;
      RECT 0.168 134.520 193.369 134.568 ;
      RECT 0.168 134.904 193.369 134.952 ;
      RECT 0.168 135.288 193.369 135.336 ;
      RECT 0.168 135.672 193.369 135.720 ;
      RECT 0.168 136.056 193.369 136.104 ;
      RECT 0.168 136.440 193.369 136.488 ;
      RECT 0.168 136.824 193.369 136.872 ;
      RECT 0.168 137.208 193.369 137.256 ;
      RECT 0.168 137.592 193.369 137.640 ;
      RECT 0.168 137.976 193.369 138.024 ;
      RECT 0.168 138.360 193.369 138.408 ;
      RECT 0.168 138.744 193.369 138.792 ;
      RECT 0.168 139.128 193.369 139.176 ;
      RECT 0.168 139.512 193.369 139.560 ;
      RECT 0.168 139.896 193.369 139.944 ;
      RECT 0.168 140.280 193.369 140.328 ;
      RECT 0.168 140.664 193.369 140.712 ;
      RECT 0.168 141.048 193.369 141.096 ;
      RECT 0.168 141.432 193.369 141.480 ;
      RECT 0.168 141.816 193.369 141.864 ;
      RECT 0.168 142.200 193.369 142.248 ;
      RECT 0.168 142.584 193.369 142.632 ;
      RECT 0.168 142.968 193.369 143.016 ;
      RECT 0.168 143.352 193.369 143.400 ;
      RECT 0.168 143.736 193.369 143.784 ;
      RECT 0.168 144.120 193.369 144.168 ;
      RECT 0.168 144.504 193.369 144.552 ;
      RECT 0.168 144.888 193.369 144.936 ;
      RECT 0.168 145.272 193.369 145.320 ;
      RECT 0.168 145.656 193.369 145.704 ;
      RECT 0.168 146.040 193.369 146.088 ;
      RECT 0.168 146.424 193.369 146.472 ;
      RECT 0.168 146.808 193.369 146.856 ;
      RECT 0.168 147.192 193.369 147.240 ;
      RECT 0.168 147.576 193.369 147.624 ;
      RECT 0.168 147.960 193.369 148.008 ;
      RECT 0.168 148.344 193.369 148.392 ;
      RECT 0.168 148.728 193.369 148.776 ;
      RECT 0.168 149.112 193.369 149.160 ;
      RECT 0.168 149.496 193.369 149.544 ;
      RECT 0.168 149.880 193.369 149.928 ;
      RECT 0.168 150.264 193.369 150.312 ;
      RECT 0.168 150.648 193.369 150.696 ;
      RECT 0.168 151.032 193.369 151.080 ;
      RECT 0.168 151.416 193.369 151.464 ;
      RECT 0.168 151.800 193.369 151.848 ;
      RECT 0.168 152.184 193.369 152.232 ;
      RECT 0.168 152.568 193.369 152.616 ;
      RECT 0.168 152.952 193.369 153.000 ;
      RECT 0.168 153.336 193.369 153.384 ;
      RECT 0.168 153.720 193.369 153.768 ;
      RECT 0.168 154.104 193.369 154.152 ;
      RECT 0.168 154.488 193.369 154.536 ;
      RECT 0.168 154.872 193.369 154.920 ;
      RECT 0.168 155.256 193.369 155.304 ;
      RECT 0.168 155.640 193.369 155.688 ;
      RECT 0.168 156.024 193.369 156.072 ;
      RECT 0.168 156.408 193.369 156.456 ;
      RECT 0.168 156.792 193.369 156.840 ;
      RECT 0.168 157.176 193.369 157.224 ;
      RECT 0.168 157.560 193.369 157.608 ;
      RECT 0.168 157.944 193.369 157.992 ;
      RECT 0.168 158.328 193.369 158.376 ;
      RECT 0.168 158.712 193.369 158.760 ;
      RECT 0.168 159.096 193.369 159.144 ;
      RECT 0.168 159.480 193.369 159.528 ;
      RECT 0.168 159.864 193.369 159.912 ;
      RECT 0.168 160.248 193.369 160.296 ;
      RECT 0.168 160.632 193.369 160.680 ;
      RECT 0.168 161.016 193.369 161.064 ;
      RECT 0.168 161.400 193.369 161.448 ;
      RECT 0.168 161.784 193.369 161.832 ;
      RECT 0.168 162.168 193.369 162.216 ;
      RECT 0.168 162.552 193.369 162.600 ;
      RECT 0.168 162.936 193.369 162.984 ;
      RECT 0.168 163.320 193.369 163.368 ;
      RECT 0.168 163.704 193.369 163.752 ;
      RECT 0.168 164.088 193.369 164.136 ;
      RECT 0.168 164.472 193.369 164.520 ;
      RECT 0.168 164.856 193.369 164.904 ;
      RECT 0.168 165.240 193.369 165.288 ;
      RECT 0.168 165.624 193.369 165.672 ;
      RECT 0.168 166.008 193.369 166.056 ;
      RECT 0.168 166.392 193.369 166.440 ;
      RECT 0.168 166.776 193.369 166.824 ;
      RECT 0.168 167.160 193.369 167.208 ;
      RECT 0.168 167.544 193.369 167.592 ;
      RECT 0.168 167.928 193.369 167.976 ;
      RECT 0.168 168.312 193.369 168.360 ;
      RECT 0.168 168.696 193.369 168.744 ;
      RECT 0.168 169.080 193.369 169.128 ;
      RECT 0.168 169.464 193.369 169.512 ;
      RECT 0.168 169.848 193.369 169.896 ;
      RECT 0.168 170.232 193.369 170.280 ;
      RECT 0.168 170.616 193.369 170.664 ;
      RECT 0.168 171.000 193.369 171.048 ;
      RECT 0.168 171.384 193.369 171.432 ;
      RECT 0.168 171.768 193.369 171.816 ;
      RECT 0.168 172.152 193.369 172.200 ;
      RECT 0.168 172.536 193.369 172.584 ;
      RECT 0.168 172.920 193.369 172.968 ;
      RECT 0.168 173.304 193.369 173.352 ;
      RECT 0.168 173.688 193.369 173.736 ;
      RECT 0.168 174.072 193.369 174.120 ;
      RECT 0.168 174.456 193.369 174.504 ;
      RECT 0.168 174.840 193.369 174.888 ;
      RECT 0.168 175.224 193.369 175.272 ;
      RECT 0.168 175.608 193.369 175.656 ;
      RECT 0.168 175.992 193.369 176.040 ;
      RECT 0.168 176.376 193.369 176.424 ;
      RECT 0.168 176.760 193.369 176.808 ;
      RECT 0.168 177.144 193.369 177.192 ;
      RECT 0.168 177.528 193.369 177.576 ;
      RECT 0.168 177.912 193.369 177.960 ;
      RECT 0.168 178.296 193.369 178.344 ;
      RECT 0.168 178.680 193.369 178.728 ;
      RECT 0.168 179.064 193.369 179.112 ;
      RECT 0.168 179.448 193.369 179.496 ;
      RECT 0.168 179.832 193.369 179.880 ;
      RECT 0.168 180.216 193.369 180.264 ;
      RECT 0.168 180.600 193.369 180.648 ;
      RECT 0.168 180.984 193.369 181.032 ;
      RECT 0.168 181.368 193.369 181.416 ;
      RECT 0.168 181.752 193.369 181.800 ;
      RECT 0.168 182.136 193.369 182.184 ;
      RECT 0.168 182.520 193.369 182.568 ;
      RECT 0.168 182.904 193.369 182.952 ;
      RECT 0.168 183.288 193.369 183.336 ;
      RECT 0.168 183.672 193.369 183.720 ;
      RECT 0.168 184.056 193.369 184.104 ;
      RECT 0.168 184.440 193.369 184.488 ;
      RECT 0.168 184.824 193.369 184.872 ;
      RECT 0.168 185.208 193.369 185.256 ;
      RECT 0.168 185.592 193.369 185.640 ;
      RECT 0.168 185.976 193.369 186.024 ;
      RECT 0.168 186.360 193.369 186.408 ;
      RECT 0.168 186.744 193.369 186.792 ;
      RECT 0.168 187.128 193.369 187.176 ;
      RECT 0.168 187.512 193.369 187.560 ;
      RECT 0.168 187.896 193.369 187.944 ;
      RECT 0.168 188.280 193.369 188.328 ;
      RECT 0.168 188.664 193.369 188.712 ;
      RECT 0.168 189.048 193.369 189.096 ;
      RECT 0.168 189.432 193.369 189.480 ;
      RECT 0.168 189.816 193.369 189.864 ;
      RECT 0.168 190.200 193.369 190.248 ;
      RECT 0.168 190.584 193.369 190.632 ;
      RECT 0.168 190.968 193.369 191.016 ;
      RECT 0.168 191.352 193.369 191.400 ;
      RECT 0.168 191.736 193.369 191.784 ;
      RECT 0.168 192.120 193.369 192.168 ;
      RECT 0.168 192.504 193.369 192.552 ;
      RECT 0.168 192.888 193.369 192.936 ;
      RECT 0.168 193.272 193.369 193.320 ;
      RECT 0.168 193.656 193.369 193.704 ;
      RECT 0.168 194.040 193.369 194.088 ;
      RECT 0.168 194.424 193.369 194.472 ;
      RECT 0.168 194.808 193.369 194.856 ;
      RECT 0.168 195.192 193.369 195.240 ;
      RECT 0.168 195.576 193.369 195.624 ;
      RECT 0.168 195.960 193.369 196.008 ;
      RECT 0.168 196.344 193.369 196.392 ;
      RECT 0.168 196.728 193.369 196.776 ;
      RECT 0.168 197.112 193.369 197.160 ;
      RECT 0.168 197.496 193.369 197.544 ;
      RECT 0.168 197.880 193.369 197.928 ;
      RECT 0.168 198.264 193.369 198.312 ;
      RECT 0.168 198.648 193.369 198.696 ;
      RECT 0.168 199.032 193.369 199.080 ;
      RECT 0.168 199.416 193.369 199.464 ;
      RECT 0.168 199.800 193.369 199.848 ;
      RECT 0.168 200.184 193.369 200.232 ;
      RECT 0.168 200.568 193.369 200.616 ;
      RECT 0.168 200.952 193.369 201.000 ;
      RECT 0.168 201.336 193.369 201.384 ;
      RECT 0.168 201.720 193.369 201.768 ;
      RECT 0.168 202.104 193.369 202.152 ;
      RECT 0.168 202.488 193.369 202.536 ;
      RECT 0.168 202.872 193.369 202.920 ;
      RECT 0.168 203.256 193.369 203.304 ;
      RECT 0.168 203.640 193.369 203.688 ;
      RECT 0.168 204.024 193.369 204.072 ;
      RECT 0.168 204.408 193.369 204.456 ;
      RECT 0.168 204.792 193.369 204.840 ;
      RECT 0.168 205.176 193.369 205.224 ;
      RECT 0.168 205.560 193.369 205.608 ;
      RECT 0.168 205.944 193.369 205.992 ;
      RECT 0.168 206.328 193.369 206.376 ;
      RECT 0.168 206.712 193.369 206.760 ;
      RECT 0.168 207.096 193.369 207.144 ;
      RECT 0.168 207.480 193.369 207.528 ;
      RECT 0.168 207.864 193.369 207.912 ;
      RECT 0.168 208.248 193.369 208.296 ;
      RECT 0.168 208.632 193.369 208.680 ;
      RECT 0.168 209.016 193.369 209.064 ;
      RECT 0.168 209.400 193.369 209.448 ;
      RECT 0.168 209.784 193.369 209.832 ;
      RECT 0.168 210.168 193.369 210.216 ;
      RECT 0.168 210.552 193.369 210.600 ;
      RECT 0.168 210.936 193.369 210.984 ;
      RECT 0.168 211.320 193.369 211.368 ;
      RECT 0.168 211.704 193.369 211.752 ;
      RECT 0.168 212.088 193.369 212.136 ;
      RECT 0.168 212.472 193.369 212.520 ;
      RECT 0.168 212.856 193.369 212.904 ;
      RECT 0.168 213.240 193.369 213.288 ;
      RECT 0.168 213.624 193.369 213.672 ;
      RECT 0.168 214.008 193.369 214.056 ;
      RECT 0.168 214.392 193.369 214.440 ;
      RECT 0.168 214.776 193.369 214.824 ;
      RECT 0.168 215.160 193.369 215.208 ;
      RECT 0.168 215.544 193.369 215.592 ;
      RECT 0.168 215.928 193.369 215.976 ;
      RECT 0.168 216.312 193.369 216.360 ;
      RECT 0.168 216.696 193.369 216.744 ;
      RECT 0.168 217.080 193.369 217.128 ;
      RECT 0.168 217.464 193.369 217.512 ;
      RECT 0.168 217.848 193.369 217.896 ;
      RECT 0.168 218.232 193.369 218.280 ;
      RECT 0.168 218.616 193.369 218.664 ;
      RECT 0.168 219.000 193.369 219.048 ;
      RECT 0.168 219.384 193.369 219.432 ;
      RECT 0.168 219.768 193.369 219.816 ;
      RECT 0.168 220.152 193.369 220.200 ;
      RECT 0.168 220.536 193.369 220.584 ;
      RECT 0.168 220.920 193.369 220.968 ;
      RECT 0.168 221.304 193.369 221.352 ;
      RECT 0.168 221.688 193.369 221.736 ;
      RECT 0.168 222.072 193.369 222.120 ;
      RECT 0.168 222.456 193.369 222.504 ;
      RECT 0.168 222.840 193.369 222.888 ;
      RECT 0.168 223.224 193.369 223.272 ;
      RECT 0.168 223.608 193.369 223.656 ;
      RECT 0.168 223.992 193.369 224.040 ;
      RECT 0.168 224.376 193.369 224.424 ;
      RECT 0.168 224.760 193.369 224.808 ;
      RECT 0.168 225.144 193.369 225.192 ;
      RECT 0.168 225.528 193.369 225.576 ;
      RECT 0.168 225.912 193.369 225.960 ;
      RECT 0.168 226.296 193.369 226.344 ;
      RECT 0.168 226.680 193.369 226.728 ;
      RECT 0.168 227.064 193.369 227.112 ;
      RECT 0.168 227.448 193.369 227.496 ;
      RECT 0.168 227.832 193.369 227.880 ;
      RECT 0.168 228.216 193.369 228.264 ;
      RECT 0.168 228.600 193.369 228.648 ;
      RECT 0.168 228.984 193.369 229.032 ;
      RECT 0.168 229.368 193.369 229.416 ;
      RECT 0.168 229.752 193.369 229.800 ;
      RECT 0.168 230.136 193.369 230.184 ;
      RECT 0.168 230.520 193.369 230.568 ;
      RECT 0.168 230.904 193.369 230.952 ;
      RECT 0.168 231.288 193.369 231.336 ;
      RECT 0.168 231.672 193.369 231.720 ;
      RECT 0.168 232.056 193.369 232.104 ;
      RECT 0.168 232.440 193.369 232.488 ;
      RECT 0.168 232.824 193.369 232.872 ;
      RECT 0.168 233.208 193.369 233.256 ;
      RECT 0.168 233.592 193.369 233.640 ;
      RECT 0.168 233.976 193.369 234.024 ;
      RECT 0.168 234.360 193.369 234.408 ;
      RECT 0.168 234.744 193.369 234.792 ;
      RECT 0.168 235.128 193.369 235.176 ;
      RECT 0.168 235.512 193.369 235.560 ;
      RECT 0.168 235.896 193.369 235.944 ;
      RECT 0.168 236.280 193.369 236.328 ;
      RECT 0.168 236.664 193.369 236.712 ;
      RECT 0.168 237.048 193.369 237.096 ;
      RECT 0.168 237.432 193.369 237.480 ;
      RECT 0.168 237.816 193.369 237.864 ;
      RECT 0.168 238.200 193.369 238.248 ;
      RECT 0.168 238.584 193.369 238.632 ;
      RECT 0.168 238.968 193.369 239.016 ;
      RECT 0.168 239.352 193.369 239.400 ;
      RECT 0.168 239.736 193.369 239.784 ;
      RECT 0.168 240.120 193.369 240.168 ;
      RECT 0.168 240.504 193.369 240.552 ;
      RECT 0.168 240.888 193.369 240.936 ;
      RECT 0.168 241.272 193.369 241.320 ;
      RECT 0.168 241.656 193.369 241.704 ;
      RECT 0.168 242.040 193.369 242.088 ;
      RECT 0.168 242.424 193.369 242.472 ;
      RECT 0.168 242.808 193.369 242.856 ;
      RECT 0.168 243.192 193.369 243.240 ;
      RECT 0.168 243.576 193.369 243.624 ;
      RECT 0.168 243.960 193.369 244.008 ;
      RECT 0.168 244.344 193.369 244.392 ;
      RECT 0.168 244.728 193.369 244.776 ;
      RECT 0.168 245.112 193.369 245.160 ;
      RECT 0.168 245.496 193.369 245.544 ;
      RECT 0.168 245.880 193.369 245.928 ;
      RECT 0.168 246.264 193.369 246.312 ;
      RECT 0.168 246.648 193.369 246.696 ;
      RECT 0.168 247.032 193.369 247.080 ;
      RECT 0.168 247.416 193.369 247.464 ;
      RECT 0.168 247.800 193.369 247.848 ;
      RECT 0.168 248.184 193.369 248.232 ;
      RECT 0.168 248.568 193.369 248.616 ;
      RECT 0.168 248.952 193.369 249.000 ;
      RECT 0.168 249.336 193.369 249.384 ;
      RECT 0.168 249.720 193.369 249.768 ;
      RECT 0.168 250.104 193.369 250.152 ;
      RECT 0.168 250.488 193.369 250.536 ;
      RECT 0.168 250.872 193.369 250.920 ;
      RECT 0.168 251.256 193.369 251.304 ;
      RECT 0.168 251.640 193.369 251.688 ;
      RECT 0.168 252.024 193.369 252.072 ;
      RECT 0.168 252.408 193.369 252.456 ;
      RECT 0.168 252.792 193.369 252.840 ;
      RECT 0.168 253.176 193.369 253.224 ;
      RECT 0.168 253.560 193.369 253.608 ;
      RECT 0.168 253.944 193.369 253.992 ;
      RECT 0.168 254.328 193.369 254.376 ;
      RECT 0.168 254.712 193.369 254.760 ;
      RECT 0.168 255.096 193.369 255.144 ;
      RECT 0.168 255.480 193.369 255.528 ;
      RECT 0.168 255.864 193.369 255.912 ;
      RECT 0.168 256.248 193.369 256.296 ;
      RECT 0.168 256.632 193.369 256.680 ;
      RECT 0.168 257.016 193.369 257.064 ;
      RECT 0.168 257.400 193.369 257.448 ;
      RECT 0.168 257.784 193.369 257.832 ;
      RECT 0.168 258.168 193.369 258.216 ;
      RECT 0.168 258.552 193.369 258.600 ;
      RECT 0.168 258.936 193.369 258.984 ;
      RECT 0.168 259.320 193.369 259.368 ;
      RECT 0.168 259.704 193.369 259.752 ;
      RECT 0.168 260.088 193.369 260.136 ;
      RECT 0.168 260.472 193.369 260.520 ;
      RECT 0.168 260.856 193.369 260.904 ;
      RECT 0.168 261.240 193.369 261.288 ;
      RECT 0.168 261.624 193.369 261.672 ;
      RECT 0.168 262.008 193.369 262.056 ;
      RECT 0.168 262.392 193.369 262.440 ;
      RECT 0.168 262.776 193.369 262.824 ;
      RECT 0.168 263.160 193.369 263.208 ;
      RECT 0.168 263.544 193.369 263.592 ;
      RECT 0.168 263.928 193.369 263.976 ;
      RECT 0.168 264.312 193.369 264.360 ;
      RECT 0.168 264.696 193.369 264.744 ;
      RECT 0.168 265.080 193.369 265.128 ;
      RECT 0.168 265.464 193.369 265.512 ;
      RECT 0.168 265.848 193.369 265.896 ;
      RECT 0.168 266.232 193.369 266.280 ;
      RECT 0.168 266.616 193.369 266.664 ;
      RECT 0.168 267.000 193.369 267.048 ;
      RECT 0.168 267.384 193.369 267.432 ;
      RECT 0.168 267.768 193.369 267.816 ;
      RECT 0.168 268.152 193.369 268.200 ;
      RECT 0.168 268.536 193.369 268.584 ;
      RECT 0.168 268.920 193.369 268.968 ;
      RECT 0.168 269.304 193.369 269.352 ;
      RECT 0.168 269.688 193.369 269.736 ;
      RECT 0.168 270.072 193.369 270.120 ;
      RECT 0.168 270.456 193.369 270.504 ;
      RECT 0.168 270.840 193.369 270.888 ;
      RECT 0.168 271.224 193.369 271.272 ;
      RECT 0.168 271.608 193.369 271.656 ;
      RECT 0.168 271.992 193.369 272.040 ;
      RECT 0.168 272.376 193.369 272.424 ;
      RECT 0.168 272.760 193.369 272.808 ;
      RECT 0.168 273.144 193.369 273.192 ;
      RECT 0.168 273.528 193.369 273.576 ;
      RECT 0.168 273.912 193.369 273.960 ;
      RECT 0.168 274.296 193.369 274.344 ;
      RECT 0.168 274.680 193.369 274.728 ;
      RECT 0.168 275.064 193.369 275.112 ;
      RECT 0.168 275.448 193.369 275.496 ;
      RECT 0.168 275.832 193.369 275.880 ;
      RECT 0.168 276.216 193.369 276.264 ;
      RECT 0.168 276.600 193.369 276.648 ;
      RECT 0.168 276.984 193.369 277.032 ;
      RECT 0.168 277.368 193.369 277.416 ;
      RECT 0.168 277.752 193.369 277.800 ;
      RECT 0.168 278.136 193.369 278.184 ;
      RECT 0.168 278.520 193.369 278.568 ;
      RECT 0.168 278.904 193.369 278.952 ;
      RECT 0.168 279.288 193.369 279.336 ;
      RECT 0.168 279.672 193.369 279.720 ;
      RECT 0.168 280.056 193.369 280.104 ;
      RECT 0.168 280.440 193.369 280.488 ;
      RECT 0.168 280.824 193.369 280.872 ;
      RECT 0.168 281.208 193.369 281.256 ;
      RECT 0.168 281.592 193.369 281.640 ;
      RECT 0.168 281.976 193.369 282.024 ;
      RECT 0.168 282.360 193.369 282.408 ;
      RECT 0.168 282.744 193.369 282.792 ;
      RECT 0.168 283.128 193.369 283.176 ;
      RECT 0.168 283.512 193.369 283.560 ;
      RECT 0.168 283.896 193.369 283.944 ;
      RECT 0.168 284.280 193.369 284.328 ;
      RECT 0.168 284.664 193.369 284.712 ;
      RECT 0.168 285.048 193.369 285.096 ;
      RECT 0.168 285.432 193.369 285.480 ;
      RECT 0.168 285.816 193.369 285.864 ;
      RECT 0.168 286.200 193.369 286.248 ;
      RECT 0.168 286.584 193.369 286.632 ;
      RECT 0.168 286.968 193.369 287.016 ;
      RECT 0.168 287.352 193.369 287.400 ;
      RECT 0.168 287.736 193.369 287.784 ;
      RECT 0.168 288.120 193.369 288.168 ;
      RECT 0.168 288.504 193.369 288.552 ;
      RECT 0.168 288.888 193.369 288.936 ;
      RECT 0.168 289.272 193.369 289.320 ;
      RECT 0.168 289.656 193.369 289.704 ;
      RECT 0.168 290.040 193.369 290.088 ;
      RECT 0.168 290.424 193.369 290.472 ;
      RECT 0.168 290.808 193.369 290.856 ;
      RECT 0.168 291.192 193.369 291.240 ;
      RECT 0.168 291.576 193.369 291.624 ;
      RECT 0.168 291.960 193.369 292.008 ;
      RECT 0.168 292.344 193.369 292.392 ;
      RECT 0.168 292.728 193.369 292.776 ;
      RECT 0.168 293.112 193.369 293.160 ;
      RECT 0.168 293.496 193.369 293.544 ;
      RECT 0.168 293.880 193.369 293.928 ;
      RECT 0.168 294.264 193.369 294.312 ;
      RECT 0.168 294.648 193.369 294.696 ;
      RECT 0.168 295.032 193.369 295.080 ;
      RECT 0.168 295.416 193.369 295.464 ;
      RECT 0.168 295.800 193.369 295.848 ;
      RECT 0.168 296.184 193.369 296.232 ;
      RECT 0.168 296.568 193.369 296.616 ;
      RECT 0.168 296.952 193.369 297.000 ;
      RECT 0.168 297.336 193.369 297.384 ;
      RECT 0.168 297.720 193.369 297.768 ;
      RECT 0.168 298.104 193.369 298.152 ;
      RECT 0.168 298.488 193.369 298.536 ;
      RECT 0.168 298.872 193.369 298.920 ;
      RECT 0.168 299.256 193.369 299.304 ;
      RECT 0.168 299.640 193.369 299.688 ;
      RECT 0.168 300.024 193.369 300.072 ;
      RECT 0.168 300.408 193.369 300.456 ;
      RECT 0.168 300.792 193.369 300.840 ;
      RECT 0.168 301.176 193.369 301.224 ;
      RECT 0.168 301.560 193.369 301.608 ;
      RECT 0.168 301.944 193.369 301.992 ;
      RECT 0.168 302.328 193.369 302.376 ;
      RECT 0.168 302.712 193.369 302.760 ;
      RECT 0.168 303.096 193.369 303.144 ;
      RECT 0.168 303.480 193.369 303.528 ;
      RECT 0.168 303.864 193.369 303.912 ;
      RECT 0.168 304.248 193.369 304.296 ;
      RECT 0.168 304.632 193.369 304.680 ;
      RECT 0.168 305.016 193.369 305.064 ;
      RECT 0.168 305.400 193.369 305.448 ;
      RECT 0.168 305.784 193.369 305.832 ;
      RECT 0.168 306.168 193.369 306.216 ;
      RECT 0.168 306.552 193.369 306.600 ;
      RECT 0.168 306.936 193.369 306.984 ;
      RECT 0.168 307.320 193.369 307.368 ;
      RECT 0.168 307.704 193.369 307.752 ;
      RECT 0.168 308.088 193.369 308.136 ;
      RECT 0.168 308.472 193.369 308.520 ;
      RECT 0.168 308.856 193.369 308.904 ;
      RECT 0.168 309.240 193.369 309.288 ;
      RECT 0.168 309.624 193.369 309.672 ;
      RECT 0.168 310.008 193.369 310.056 ;
      RECT 0.168 310.392 193.369 310.440 ;
      RECT 0.168 310.776 193.369 310.824 ;
      RECT 0.168 311.160 193.369 311.208 ;
      RECT 0.168 311.544 193.369 311.592 ;
      RECT 0.168 311.928 193.369 311.976 ;
      RECT 0.168 312.312 193.369 312.360 ;
      RECT 0.168 312.696 193.369 312.744 ;
      RECT 0.168 313.080 193.369 313.128 ;
      RECT 0.168 313.464 193.369 313.512 ;
      RECT 0.168 313.848 193.369 313.896 ;
      RECT 0.168 314.232 193.369 314.280 ;
      RECT 0.168 314.616 193.369 314.664 ;
      RECT 0.168 315.000 193.369 315.048 ;
      RECT 0.168 315.384 193.369 315.432 ;
      RECT 0.168 315.768 193.369 315.816 ;
      RECT 0.168 316.152 193.369 316.200 ;
      RECT 0.168 316.536 193.369 316.584 ;
      RECT 0.168 316.920 193.369 316.968 ;
      RECT 0.168 317.304 193.369 317.352 ;
      RECT 0.168 317.688 193.369 317.736 ;
      RECT 0.168 318.072 193.369 318.120 ;
      RECT 0.168 318.456 193.369 318.504 ;
      RECT 0.168 318.840 193.369 318.888 ;
      RECT 0.168 319.224 193.369 319.272 ;
      RECT 0.168 319.608 193.369 319.656 ;
      RECT 0.168 319.992 193.369 320.040 ;
      RECT 0.168 320.376 193.369 320.424 ;
      RECT 0.168 320.760 193.369 320.808 ;
      RECT 0.168 321.144 193.369 321.192 ;
      RECT 0.168 321.528 193.369 321.576 ;
      RECT 0.168 321.912 193.369 321.960 ;
      RECT 0.168 322.296 193.369 322.344 ;
      RECT 0.168 322.680 193.369 322.728 ;
      RECT 0.168 323.064 193.369 323.112 ;
      RECT 0.168 323.448 193.369 323.496 ;
      RECT 0.168 323.832 193.369 323.880 ;
      RECT 0.168 324.216 193.369 324.264 ;
      RECT 0.168 324.600 193.369 324.648 ;
      RECT 0.168 324.984 193.369 325.032 ;
      RECT 0.168 325.368 193.369 325.416 ;
      RECT 0.168 325.752 193.369 325.800 ;
      RECT 0.168 326.136 193.369 326.184 ;
      RECT 0.168 326.520 193.369 326.568 ;
      RECT 0.168 326.904 193.369 326.952 ;
      RECT 0.168 327.288 193.369 327.336 ;
      RECT 0.168 327.672 193.369 327.720 ;
      RECT 0.168 328.056 193.369 328.104 ;
      RECT 0.168 328.440 193.369 328.488 ;
      RECT 0.168 328.824 193.369 328.872 ;
      RECT 0.168 329.208 193.369 329.256 ;
      RECT 0.168 329.592 193.369 329.640 ;
      RECT 0.168 329.976 193.369 330.024 ;
      RECT 0.168 330.360 193.369 330.408 ;
      RECT 0.168 330.744 193.369 330.792 ;
      RECT 0.168 331.128 193.369 331.176 ;
      RECT 0.168 331.512 193.369 331.560 ;
    END
  END VDD
  OBS
    LAYER M1 ;
    RECT 0 0 193.537 331.776 ;
    LAYER M2 ;
    RECT 0 0 193.537 331.776 ;
    LAYER M3 ;
    RECT 0 0 193.537 331.776 ;
    LAYER M4 ;
    RECT 0 0 193.537 331.776 ;
  END
END fakeram_w16_l32768

END LIBRARY
